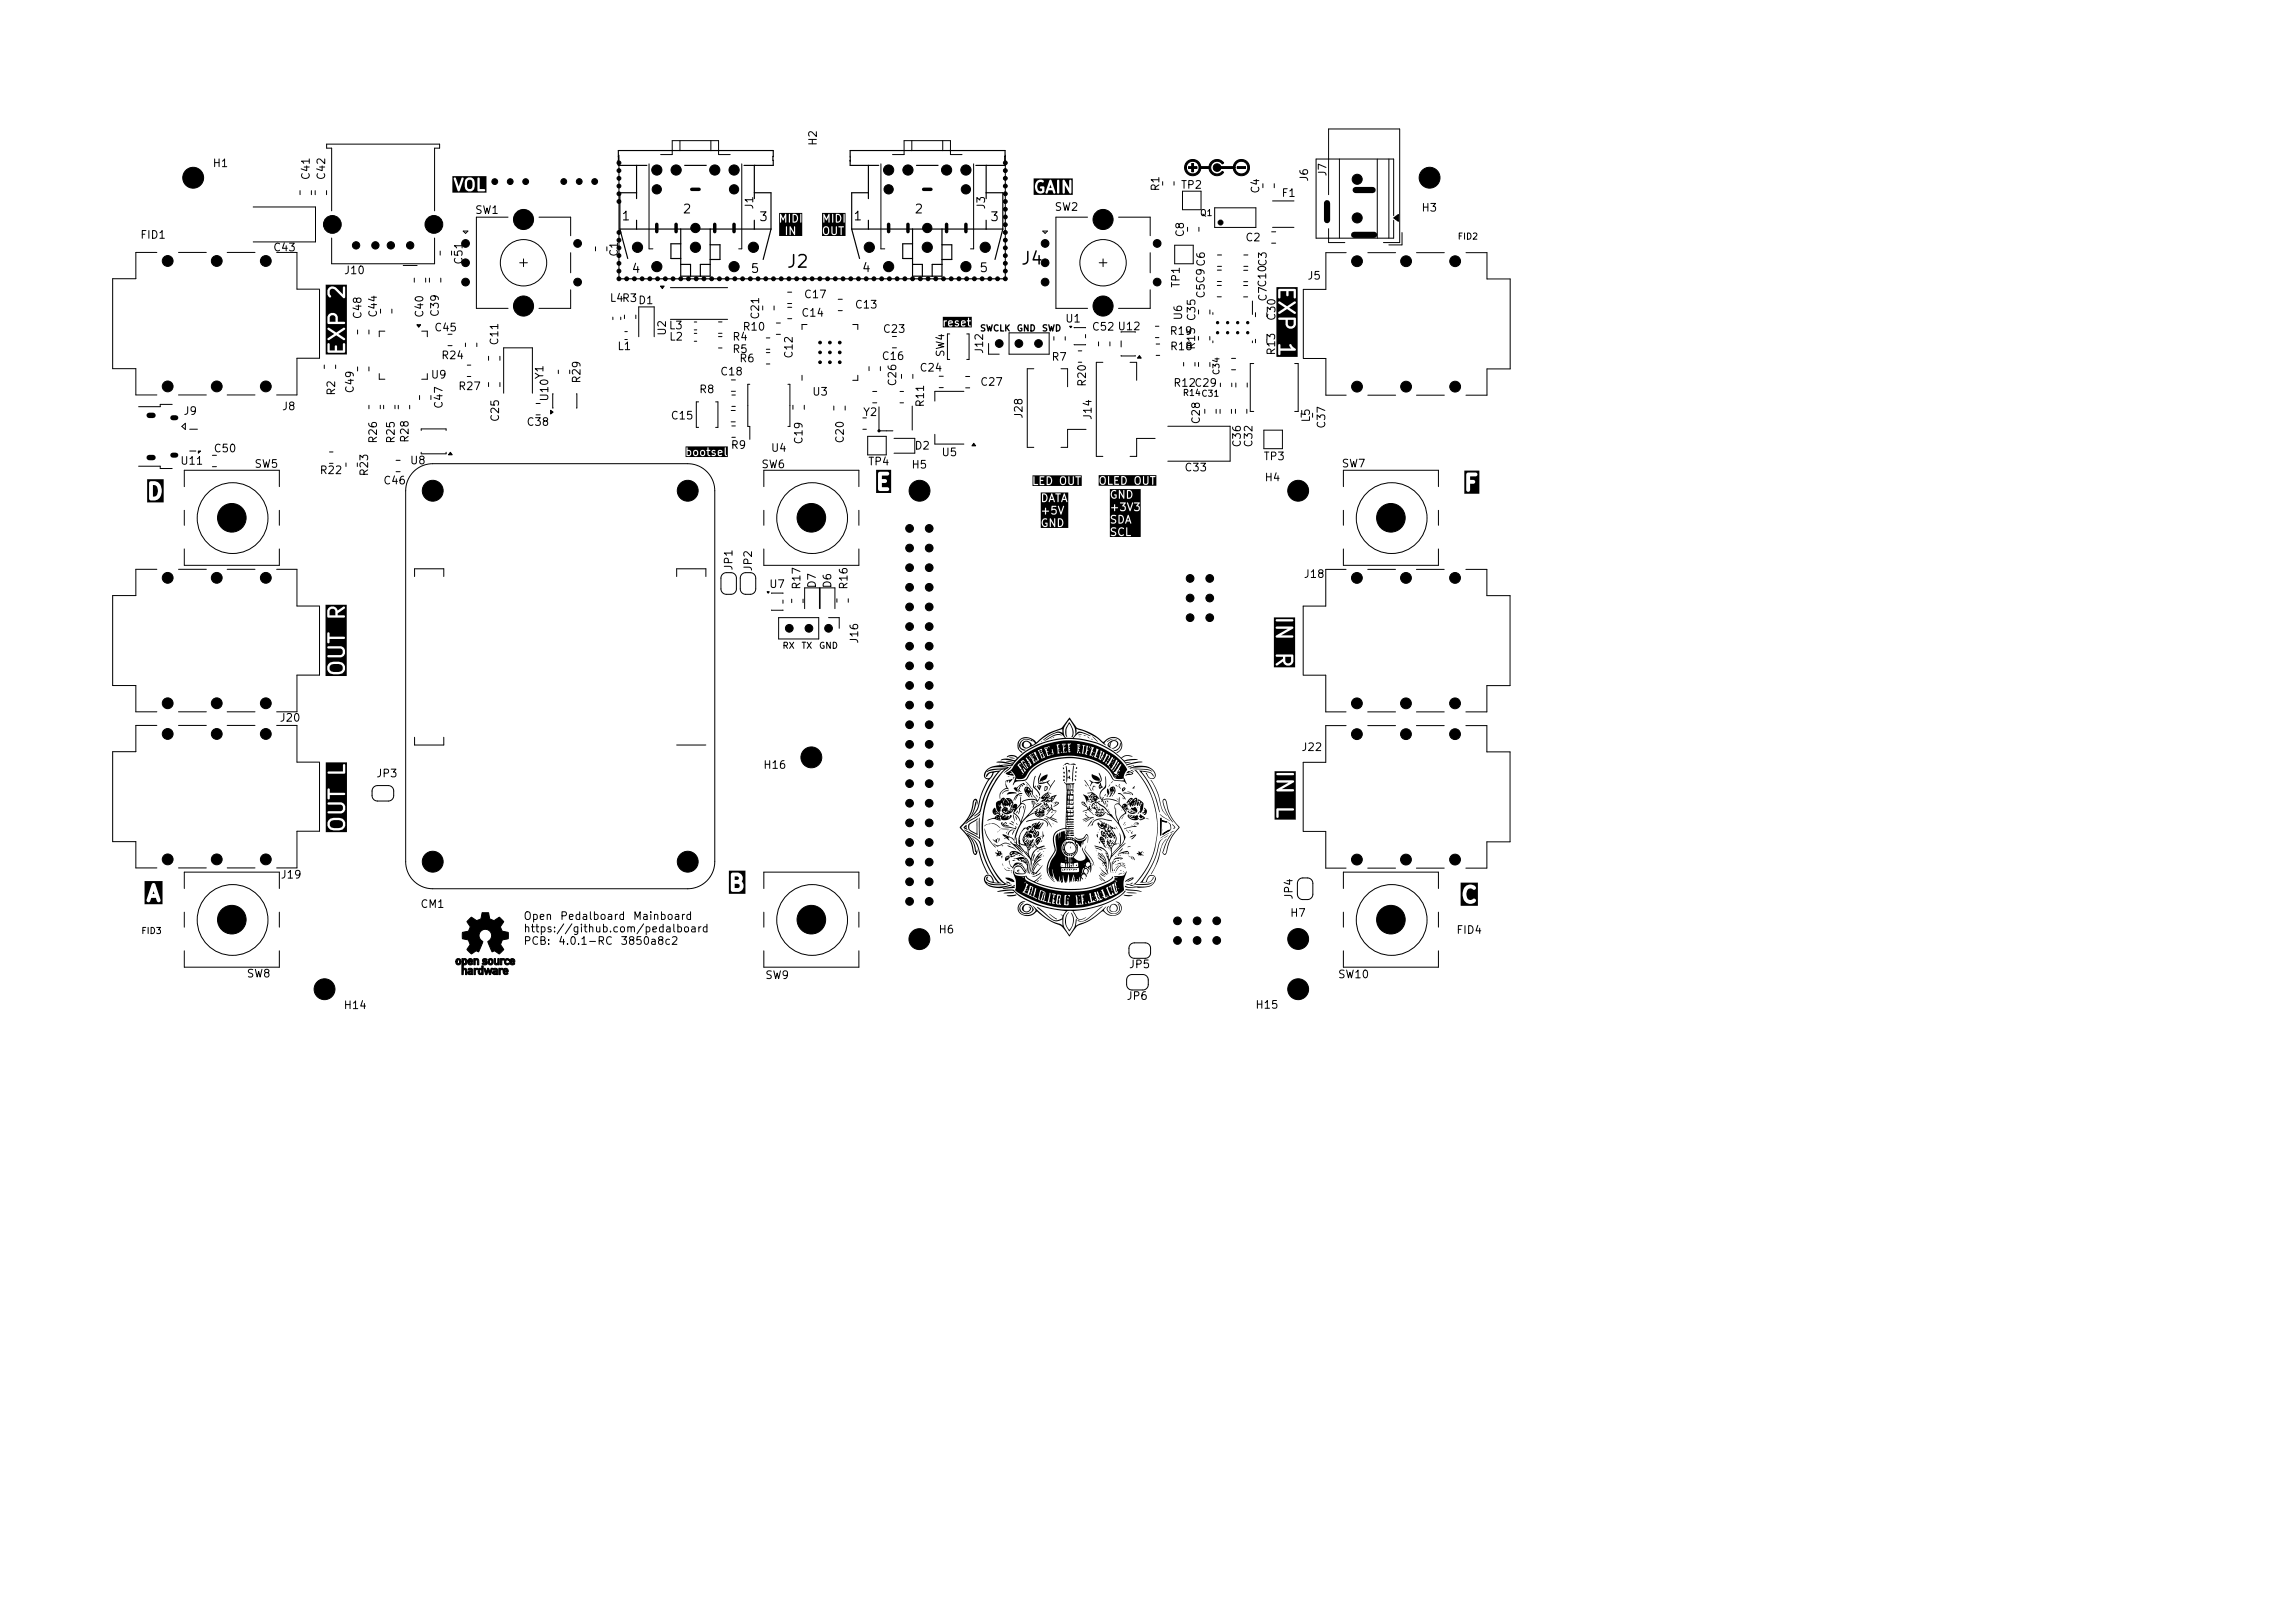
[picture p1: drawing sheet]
<svg xmlns="http://www.w3.org/2000/svg" width="297mm" height="210mm" viewBox="0 0 297 210" stroke-linecap="round" stroke-linejoin="round" font-family="sans-serif">
<defs><g id="words">
<g font-size="1.6">
<text x="101.7" y="35">J2</text>
<text x="132" y="34.6">J4</text>
</g>
<g font-size="1.1">
<text x="80.4" y="28.8">1</text>
<text x="88.3" y="27.9">2</text>
<text x="98.2" y="28.9">3</text>
<text x="110.4" y="28.8">1</text>
<text x="118.3" y="27.9">2</text>
<text x="128.1" y="28.9">3</text>
<text x="81.7" y="35.6">4</text>
<text x="97.1" y="35.6">5</text>
<text x="111.5" y="35.5">4</text>
<text x="126.7" y="35.5">5</text>
</g>
<g font-size="1">
<text x="27.4" y="21.9">H1</text>
<text x="40.3" y="23.4" transform="rotate(-90 40.3 23.4)">C41</text>
<text x="42.3" y="23.4" transform="rotate(-90 42.3 23.4)">C42</text>
<text x="105.9" y="19" transform="rotate(-90 105.9 19)">H2</text>
<text x="169.5" y="23.6" transform="rotate(-90 169.5 23.6)">J6</text>
<text x="171.9" y="22.9" transform="rotate(-90 171.9 22.9)">J7</text>
<text x="61.4" y="27.9">SW1</text>
<text x="97.7" y="27.2" transform="rotate(-90 97.7 27.2)">J1</text>
<text x="127.7" y="27.2" transform="rotate(-90 127.7 27.2)">J3</text>
<text x="136.4" y="27.5">SW2</text>
<text x="150.3" y="24.8" transform="rotate(-90 150.3 24.8)">R1</text>
<text x="152.7" y="24.7">TP2</text>
<text x="163.2" y="25.1" transform="rotate(-90 163.2 25.1)">C4</text>
<text x="165.8" y="25.7">F1</text>
<text x="183.9" y="27.6">H3</text>
<text x="18.1" y="31.1">FID1</text>
<text x="35.3" y="32.8">C43</text>
<text x="44.4" y="35.7">J10</text>
<text x="60.1" y="34.3" transform="rotate(-90 60.1 34.3)">C51</text>
<text x="80.2" y="33.3" transform="rotate(-90 80.2 33.3)">C1</text>
<text x="153.5" y="30.8" transform="rotate(-90 153.5 30.8)">C8</text>
<text x="161.1" y="31.5">C2</text>
<text x="47" y="41.4" transform="rotate(-90 47 41.4)">C48</text>
<text x="49" y="41.2" transform="rotate(-90 49 41.2)">C44</text>
<text x="55" y="41.2" transform="rotate(-90 55 41.2)">C40</text>
<text x="57" y="41.1" transform="rotate(-90 57 41.1)">C39</text>
<text x="78.8" y="39.3">L4R3</text>
<text x="82.5" y="39.6">D1</text>
<text x="98.5" y="41.4" transform="rotate(-90 98.5 41.4)">C21</text>
<text x="103.6" y="41.2">C14</text>
<text x="104" y="38.8">C17</text>
<text x="110.6" y="40.2">C13</text>
<text x="137.8" y="42">U1</text>
<text x="152.9" y="37.3" transform="rotate(-90 152.9 37.3)">TP1</text>
<text x="153.2" y="41.5" transform="rotate(-90 153.2 41.5)">U6</text>
<text x="156.2" y="38.7" transform="rotate(-90 156.2 38.7)">C5C9C6</text>
<text x="164.2" y="39.1" transform="rotate(-90 164.2 39.1)">C7C10C3</text>
<text x="165.3" y="41.6" transform="rotate(-90 165.3 41.6)">C30</text>
<text x="169.1" y="36.4">J5</text>
<text x="56.1" y="43.1">C45</text>
<text x="57" y="46.7">R24</text>
<text x="64.7" y="44.8" transform="rotate(-90 64.7 44.8)">C11</text>
<text x="79.8" y="45.5">L1</text>
<text x="86.4" y="43.5" transform="rotate(-90 86.4 43.5)">U2</text>
<text x="86.5" y="42.9">L3</text>
<text x="86.5" y="44.3">L2</text>
<text x="94.7" y="44.3">R4</text>
<text x="94.7" y="45.9">R5</text>
<text x="95.6" y="47.1">R6</text>
<text x="96" y="43">R10</text>
<text x="102.8" y="46.5" transform="rotate(-90 102.8 46.5)">C12</text>
<text x="114" y="46.8">C16</text>
<text x="114.2" y="43.3">C23</text>
<text x="122.5" y="46.3" transform="rotate(-90 122.5 46.3)">SW4</text>
<text x="127.5" y="45.9" transform="rotate(-90 127.5 45.9)">J12</text>
<text x="136" y="46.9">R7</text>
<text x="141.2" y="43">C52 U12</text>
<text x="151.3" y="43.6">R19</text>
<text x="151.3" y="45.6">R18</text>
<text x="154.9" y="45.3" transform="rotate(-90 154.9 45.3)">R15 C35</text>
<text x="165.3" y="46.1" transform="rotate(-90 165.3 46.1)">R13</text>
<text x="23.7" y="53.9">J9</text>
<text x="36.4" y="53.3">J8</text>
<text x="43.6" y="51.3" transform="rotate(-90 43.6 51.3)">R2</text>
<text x="46" y="51" transform="rotate(-90 46 51)">C49</text>
<text x="55.7" y="49.2">U9</text>
<text x="57.5" y="53" transform="rotate(-90 57.5 53)">C47</text>
<text x="59.2" y="50.7">R27</text>
<text x="70.6" y="49.1" transform="rotate(-90 70.6 49.1)">Y1</text>
<text x="71.2" y="52" transform="rotate(-90 71.2 52)">U10</text>
<text x="75.4" y="49.7" transform="rotate(-90 75.4 49.7)">R29</text>
<text x="90.4" y="51.1">R8</text>
<text x="93.1" y="48.8">C18</text>
<text x="105" y="51.4">U3</text>
<text x="116.2" y="50.1" transform="rotate(-90 116.2 50.1)">C26</text>
<text x="118.9" y="48.3">C24</text>
<text x="119.8" y="52.8" transform="rotate(-90 119.8 52.8)">R11</text>
<text x="126.8" y="50.2">C27</text>
<text x="140.8" y="50.1" transform="rotate(-90 140.8 50.1)">R20</text>
<text x="151.8" y="50.3">R12C29</text>
<text x="27.6" y="58.8">C50</text>
<text x="49" y="57.5" transform="rotate(-90 49 57.5)">R26</text>
<text x="51.3" y="57.5" transform="rotate(-90 51.3 57.5)">R25</text>
<text x="53.1" y="57.4" transform="rotate(-90 53.1 57.4)">R28</text>
<text x="64.8" y="54.7" transform="rotate(-90 64.8 54.7)">C25</text>
<text x="68.1" y="55.3">C38</text>
<text x="86.7" y="54.5">C15</text>
<text x="94.5" y="58.3">R9</text>
<text x="99.7" y="58.7">U4</text>
<text x="104.1" y="57.6" transform="rotate(-90 104.1 57.6)">C19</text>
<text x="109.4" y="57.5" transform="rotate(-90 109.4 57.5)">C20</text>
<text x="111.6" y="54.1">Y2</text>
<text x="118.3" y="58.4">D2</text>
<text x="121.8" y="59.3">U5</text>
<text x="132.6" y="54.3" transform="rotate(-90 132.6 54.3)">J28</text>
<text x="141.5" y="54.4" transform="rotate(-90 141.5 54.4)">J14</text>
<text x="155.5" y="55" transform="rotate(-90 155.5 55)">C28</text>
<text x="160.8" y="58" transform="rotate(-90 160.8 58)">C36</text>
<text x="162.3" y="58" transform="rotate(-90 162.3 58)">C32</text>
<text x="163.4" y="59.8">TP3</text>
<text x="169.8" y="54.7" transform="rotate(-90 169.8 54.7)">L5</text>
<text x="171.8" y="55.5" transform="rotate(-90 171.8 55.5)">C37</text>
<text x="23.2" y="60.4">U11</text>
<text x="32.9" y="60.8">SW5</text>
<text x="41.3" y="61.6">R22</text>
<text x="47.9" y="61.7" transform="rotate(-90 47.9 61.7)">R23</text>
<text x="49.5" y="62.9">C46</text>
<text x="53" y="60.3">U8</text>
<text x="98.5" y="60.8">SW6</text>
<text x="112.3" y="60.5">TP4</text>
<text x="117.9" y="60.9">H5</text>
<text x="153.2" y="61.2">C33</text>
<text x="163.6" y="62.5">H4</text>
<text x="173.6" y="60.7">SW7</text>
<text x="95" y="73.9" transform="rotate(-90 95 73.9)">JP1</text>
<text x="97.6" y="74" transform="rotate(-90 97.6 74)">JP2</text>
<text x="99.5" y="76.3">U7</text>
<text x="103.8" y="76.4" transform="rotate(-90 103.8 76.4)">R17</text>
<text x="105.8" y="76.2" transform="rotate(-90 105.8 76.2)">D7</text>
<text x="107.8" y="76.2" transform="rotate(-90 107.8 76.2)">D6</text>
<text x="109.9" y="76.4" transform="rotate(-90 109.9 76.4)">R16</text>
<text x="168.6" y="75">J18</text>
<text x="111.3" y="83.4" transform="rotate(-90 111.3 83.4)">J16</text>
<text x="36.1" y="93.6">J20</text>
<text x="48.6" y="100.8">JP3</text>
<text x="98.7" y="99.7">H16</text>
<text x="168.3" y="97.4">J22</text>
<text x="36.2" y="113.9">J19</text>
<text x="54.3" y="117.7">CM1</text>
<text x="67.7" y="119.3">Open</text>
<text x="72.4" y="119.3">Pedalboard</text>
<text x="81.8" y="119.3">Mainboard</text>
<text x="166.9" y="118.9">H7</text>
<text x="167.5" y="116.5" transform="rotate(-90 167.5 116.5)">JP4</text>
<text x="67.7" y="120.9">https://github.com/pedalboard</text>
<text x="67.7" y="122.5">PCB:</text>
<text x="72.2" y="122.5">4.0.1-RC</text>
<text x="80.2" y="122.5">3850a8c2</text>
<text x="121.4" y="121">H6</text>
<text x="146" y="125.5">JP5</text>
<text x="188.4" y="121.1">FID4</text>
<text x="31.9" y="126.7">SW8</text>
<text x="44.4" y="130.8">H14</text>
<text x="99" y="126.9">SW9</text>
<text x="145.7" y="129.6">JP6</text>
<text x="162.4" y="130.8">H15</text>
<text x="173.1" y="126.8">SW10</text>
</g>
<g font-size=".8">
<text x="155.2" y="28.1">Q1</text>
<text x="188.6" y="31.2">FID2</text>
<text x="126.8" y="43.1">SWCLK</text>
<text x="131.5" y="43.1">GND</text>
<text x="134.8" y="43.1">SWD</text>
<text x="153" y="51.4">R14C31</text>
<text x="158" y="48.6" transform="rotate(-90 158 48.6)">C34</text>
<text x="101.2" y="84.1">RX</text>
<text x="103.7" y="84.1">TX</text>
<text x="105.9" y="84.1">GND</text>
<text x="18.2" y="121">FID3</text>
</g>
</g></defs>
<g fill="#000" stroke="#000" stroke-width=".13">
<path d="M85.5 37h.5l-.3 .3zM153.6 20.9l.3-.2 .5-.1 .4 .1 .3 .2 .2 .4 .1 .4-.1 .4-.2 .3-.3 .3h-.4h-.5l-.3-.3-.2-.3-.1-.4h.2l.1 .3 .3 .3 .5 .2 .5-.2 .3-.6-.3-.6-.5-.2-.6 .2-.2 .2-.1 .4h-.2l.1-.4zM154.2 21.2h.3v1h-.3zM153.8 21.6h1.1v.2h-1.1zM155.3 21.6h1.2v.2h-1.2zM156.8 20.9l.3-.2 .4-.1 .4 .1 .4 .3 .1 .1-.2 .1-.5-.3h-.5l-.4 .3-.1 .4 .1 .5 .3 .3 .6 .1 .5-.3 .2 .1-.2 .1-.3 .2-.4 .1h-.4l-.3-.3-.3-.3v-.4v-.4zM157.8 21.6h1.8v.2h-1.8zM159.9 20.9l.3-.2 .5-.1 .4 .1 .3 .2 .2 .4 .1 .4-.1 .4-.2 .3-.3 .3h-.4h-.5l-.3-.3-.2-.3-.1-.4h.2l.1 .3 .3 .3 .5 .2 .5-.2 .3-.6-.3-.6-.5-.2-.6 .2-.2 .2-.1 .4h-.2l.1-.4zM160.1 21.6h1.1v.2h-1.1zM180.4 28.2l.6-.4v.8zM25.7 58.4h.2l-.2 .2zM54 42h.4l-.2 .3z"/>
<path d="M58.3 58.5l.2 .4h-.5zM71.3 53.1l.3 .2-.3 .3zM126 57.4l.3 .3h-.5zM138.4 42.2h.3l-.1 .2zM147.5 46l.2 .3h-.5zM99.3 76.6h.3l-.2 .2zM60.8 118.9l.1-.1a.18 .18 0 0 1 .1-.1 .18 .18 0 0 1 .2 .1l.5 .3 .5-.2 .2-.8h.8l.2 .8 .5 .2 .5-.3a.17 .17 0 0 1 .2-.1 .17 .17 0 0 1 .2 .1l.2 .2a.26 .26 0 0 1 .2 .3 .26 .26 0 0 1-.2 .2v.1a.6 .6 0 0 0 .1 .9l.4 .1a.26 .26 0 0 1 .3 .1 .26 .26 0 0 1 0 .3v.2a.23 .23 0 0 1 0 .3 .23 .23 0 0 1-.3 0 .58 .58 0 0 0-.7 .7l.3 .4a.25 .25 0 0 1 .1 .3 .25 .25 0 0 1-.2 .2l-.2 .2a.2 .2 0 0 1-.2 .1 .2 .2 0 0 1-.2-.1l-.1-.1a.46 .46 0 0 0-.6 0l-.5-1a.21 .21 0 0 1-.1-.2 .21 .21 0 0 1 .1-.2 .82 .82 0 0 0 .2-1.3 .82 .82 0 0 0-1.3 .1 .82 .82 0 0 0 .4 1.2l-.6 1.4a.52 .52 0 0 0-.7 .1 .24 .24 0 0 1-.3 .1 .24 .24 0 0 1-.1-.2h-.1a.29 .29 0 0 1-.2-.4l.1-.1a.68 .68 0 0 0 .1-.9 .68 .68 0 0 0-.8-.3 .21 .21 0 0 1-.1-.4v-.2a.26 .26 0 0 1 .1-.3 .26 .26 0 0 1 .3 0 .6 .6 0 0 0 .6-.7l-.3-.5a.17 .17 0 0 1-.1-.2 .17 .17 0 0 1 .2-.1zM150.2 105.9v2.2zM150.4 106.2l.6 .2-.4-.1zM150.5 107.9l.9-.5zM59.1 124.1a.38 .38 0 0 1 .5 .1 .38 .38 0 0 1-.1 .5 .38 .38 0 0 1-.5-.1v-.2h.2a.19 .19 0 0 0 .2 .3 .19 .19 0 0 0 .1-.3 .15 .15 0 0 0-.2-.2 .15 .15 0 0 0-.1 .1v.1h-.2zM59.8 124l.2 .1a.33 .33 0 0 1 .4 .1 .33 .33 0 0 1 0 .3 .27 .27 0 0 1-.1 .3 .27 .27 0 0 1-.3 0v.5h.2l.2 .2v.6h-.2v-.6a.18 .18 0 0 0-.2 0 .18 .18 0 0 0 0 .3v.3h-.2v-1.6h.2a.17 .17 0 0 0 .2 .1 .17 .17 0 0 0 0-.2v-.1a.13 .13 0 0 0-.1-.1 .13 .13 0 0 0-.1 .1v.2h-.2z"/>
<path d="M60.6 125.4a.37 .37 0 0 1 .5-.1 .37 .37 0 0 1 .1 .5v.3h-.3a.28 .28 0 0 1-.4-.3l.2 .1a.16 .16 0 0 0 .2 0 .16 .16 0 0 0 .1-.1h-.3h-.2a.34 .34 0 0 1 .5-.2 .2 .2 0 0 0-.1-.1 .2 .2 0 0 0-.2 0zM60.6 124.1a.36 .36 0 0 1 .5 0 .36 .36 0 0 1 .1 .4h-.5a.21 .21 0 0 0 .1 .2 .21 .21 0 0 0 .3-.1l.1 .1a.36 .36 0 0 1-.5 .1 .36 .36 0 0 1-.2-.5h.5a.16 .16 0 0 0-.2-.1 .16 .16 0 0 0-.1 .1h-.2zM61.3 125.3l.6 .1-.4 .1v.6h-.2zM61.3 124h.1a.48 .48 0 0 1 .6 .3v.5h-.2v-.3a.18 .18 0 0 0-.2-.3 .17 .17 0 0 0-.1 .3v.3h-.2zM62 125.3l.3 .1v-.4h.2v1.1h-.2a.3 .3 0 0 1-.3-.1 .3 .3 0 0 1-.1-.3h.2a.17 .17 0 0 0 .2 .2 .17 .17 0 0 0 0-.3 .16 .16 0 0 0-.1-.1 .16 .16 0 0 0-.1 .2h-.2zM62.5 124.1l.3-.1 .2 .1a.15 .15 0 0 1-.1 .2 .15 .15 0 0 1-.1-.1h-.2v.1a.32 .32 0 0 1 .5 .4 .31 .31 0 0 1-.5 .1l-.2-.1 .1-.1a.19 .19 0 0 0 .2 .1 .19 .19 0 0 0 .2-.2 .3 .3 0 0 1-.4 0 .3 .3 0 0 1 0-.4zM62.6 125.3h.2l.1 .5 .2-.5h.1l.2 .5 .2-.5h.1l-.2 .8h-.2l-.1-.5-.2 .5h-.1zM63.2 124.1a.4 .4 0 0 1 .6 .2 .4 .4 0 0 1-.2 .5 .35 .35 0 0 1-.4-.4h.1v.1a.16 .16 0 0 0 .2 .2 .16 .16 0 0 0 .2-.2 .18 .18 0 0 0-.2-.3 .17 .17 0 0 0-.2 .2h-.1zM64 124h.1v.3a.22 .22 0 0 0 0 .3 .22 .22 0 0 0 .3 .1v-.7h.2v.8h-.2a.33 .33 0 0 1-.4 0 .33 .33 0 0 1 0-.4zM63.8 125.4a.37 .37 0 0 1 .5-.1 .37 .37 0 0 1 .1 .5v.3h-.2a.29 .29 0 0 1-.5-.2h.2a.17 .17 0 0 0 .2 0 .17 .17 0 0 0 .1-.1l-.5 .1 .2-.3h.3a.25 .25 0 0 0-.3-.1zM64.6 125.3l.5 .1-.2 .1a.22 .22 0 0 0-.2 .1 .22 .22 0 0 0 0 .2v.3h-.1zM64.8 124l.5 .1-.1 .1-.3 .1v.5h-.1z"/>
<path d="M65.2 125.4a.36 .36 0 0 1 .4-.1 .36 .36 0 0 1 .2 .5h-.5l.1 .1h.2l.1 .1a.36 .36 0 0 1-.4 .1 .36 .36 0 0 1-.2-.5h.5a.15 .15 0 0 0-.2-.1 .15 .15 0 0 0-.1 .1h-.2zM65.4 124.1a.28 .28 0 0 1 .3-.1 .28 .28 0 0 1 .2 .2l-.1 .1a.23 .23 0 0 0-.3 0 .23 .23 0 0 0 0 .4 .23 .23 0 0 0 .4-.1v.1a.41 .41 0 0 1-.5 0 .41 .41 0 0 1 0-.6zM66.1 124.1a.35 .35 0 0 1 .4 0 .35 .35 0 0 1 .1 .4h-.5a.2 .2 0 0 0 .2 .2 .2 .2 0 0 0 .2-.1l.1 .1a.38 .38 0 0 1-.5 .1 .38 .38 0 0 1-.1-.5h.5a.16 .16 0 0 0-.2-.1 .16 .16 0 0 0-.2 .1h-.1z"/>
<circle cx="21.7" cy="33.8" r=".7"/>
<circle cx="25" cy="23" r="1.35"/>
<circle cx="28" cy="33.8" r=".7"/>
<circle cx="34.4" cy="33.8" r=".7"/>
<circle cx="43" cy="29" r="1.15"/>
<circle cx="46.1" cy="31.8" r=".47"/>
<circle cx="48.6" cy="31.8" r=".47"/>
<circle cx="50.6" cy="31.8" r=".47"/>
<circle cx="53.1" cy="31.8" r=".47"/>
<circle cx="56.1" cy="29" r="1.15"/>
<circle cx="60.2" cy="36.5" r=".5"/>
<circle cx="60.2" cy="31.5" r=".5"/>
<circle cx="60.2" cy="34" r=".5"/>
<circle cx="64" cy="23.5" r=".38"/>
<circle cx="66" cy="23.5" r=".38"/>
<circle cx="67.7" cy="28.4" r="1.3"/>
<circle cx="67.7" cy="39.6" r="1.3"/>
<circle cx="68" cy="23.5" r=".38"/>
<circle cx="73" cy="23.5" r=".37"/>
<circle cx="74.8" cy="36.5" r=".5"/>
<circle cx="74.8" cy="31.5" r=".5"/>
<circle cx="75" cy="23.5" r=".37"/>
<circle cx="77" cy="23.5" r=".37"/>
<circle cx="80.1" cy="22.1" r=".25"/>
<circle cx="80.1" cy="25.1" r=".25"/>
<circle cx="80.1" cy="23.1" r=".25"/>
<circle cx="80.1" cy="24.1" r=".25"/>
<circle cx="80.1" cy="21.1" r=".25"/>
<circle cx="80.1" cy="26.1" r=".25"/>
<circle cx="80.1" cy="32.1" r=".25"/>
<circle cx="80.1" cy="33.1" r=".25"/>
<circle cx="80.1" cy="35.1" r=".25"/>
<circle cx="80.1" cy="30.1" r=".25"/>
<circle cx="80.1" cy="34.1" r=".25"/>
<circle cx="80.1" cy="31.1" r=".25"/>
<circle cx="80.1" cy="36.1" r=".25"/>
<circle cx="81.1" cy="36.1" r=".25"/>
<circle cx="82.1" cy="36.1" r=".25"/>
<circle cx="82.5" cy="32" r=".66"/>
<circle cx="83.1" cy="36.1" r=".25"/>
<circle cx="84.1" cy="36.1" r=".25"/>
<circle cx="85" cy="24.5" r=".6"/>
<circle cx="85" cy="34.5" r=".66"/>
<circle cx="85" cy="22" r=".66"/>
<circle cx="85.1" cy="36.1" r=".25"/>
<circle cx="86.1" cy="36.1" r=".25"/>
<circle cx="87.1" cy="36.1" r=".25"/>
<circle cx="87.5" cy="22" r=".66"/>
<circle cx="88.1" cy="36.1" r=".25"/>
<circle cx="89.1" cy="36.1" r=".25"/>
<circle cx="90" cy="29.5" r=".6"/>
<circle cx="90" cy="32" r=".66"/>
<circle cx="90.1" cy="36.1" r=".25"/>
<circle cx="91.1" cy="36.1" r=".25"/>
<circle cx="92.1" cy="36.1" r=".25"/>
<circle cx="92.5" cy="22" r=".66"/>
<circle cx="93.1" cy="36.1" r=".25"/>
<circle cx="94.1" cy="36.1" r=".25"/>
<circle cx="95" cy="24.5" r=".6"/>
<circle cx="95" cy="34.5" r=".66"/>
<circle cx="95" cy="22" r=".66"/>
<circle cx="95.1" cy="36.1" r=".25"/>
<circle cx="96.1" cy="36.1" r=".25"/>
<circle cx="97.1" cy="36.1" r=".25"/>
<circle cx="97.5" cy="32" r=".66"/>
<circle cx="98.1" cy="36.1" r=".25"/>
<circle cx="99.1" cy="36.1" r=".25"/>
<circle cx="100.1" cy="36.1" r=".25"/>
<circle cx="101.1" cy="36.1" r=".25"/>
<circle cx="102.1" cy="36.1" r=".25"/>
<circle cx="103.1" cy="36.1" r=".25"/>
<circle cx="104.1" cy="36.1" r=".25"/>
<circle cx="105.1" cy="36.1" r=".25"/>
<circle cx="106.1" cy="36.1" r=".25"/>
<circle cx="107.1" cy="36.1" r=".25"/>
<circle cx="108.1" cy="36.1" r=".25"/>
<circle cx="109.1" cy="36.1" r=".25"/>
<circle cx="110.1" cy="36.1" r=".25"/>
<circle cx="111.1" cy="36.1" r=".25"/>
<circle cx="112.1" cy="36.1" r=".25"/>
<circle cx="112.5" cy="32" r=".66"/>
<circle cx="113.1" cy="36.1" r=".25"/>
<circle cx="114.1" cy="36.1" r=".25"/>
<circle cx="115" cy="34.5" r=".66"/>
<circle cx="115" cy="22" r=".66"/>
<circle cx="115" cy="24.5" r=".6"/>
<circle cx="115.1" cy="36.1" r=".25"/>
<circle cx="116.1" cy="36.1" r=".25"/>
<circle cx="117.1" cy="36.1" r=".25"/>
<circle cx="117.5" cy="22" r=".66"/>
<circle cx="118.1" cy="36.1" r=".25"/>
<circle cx="119.1" cy="36.1" r=".25"/>
<circle cx="120" cy="29.5" r=".6"/>
<circle cx="120" cy="32" r=".66"/>
<circle cx="120.1" cy="36.1" r=".25"/>
<circle cx="121.1" cy="36.1" r=".25"/>
<circle cx="122.1" cy="36.1" r=".25"/>
<circle cx="122.5" cy="22" r=".66"/>
<circle cx="123.1" cy="36.1" r=".25"/>
<circle cx="124.1" cy="36.1" r=".25"/>
<circle cx="125" cy="34.5" r=".66"/>
<circle cx="125" cy="22" r=".66"/>
<circle cx="125" cy="24.5" r=".6"/>
<circle cx="125.1" cy="36.1" r=".25"/>
<circle cx="126.1" cy="36.1" r=".25"/>
<circle cx="127.1" cy="36.1" r=".25"/>
<circle cx="127.5" cy="32" r=".66"/>
<circle cx="128.1" cy="36.1" r=".25"/>
<circle cx="129.1" cy="36.1" r=".25"/>
<circle cx="130.1" cy="28.1" r=".25"/>
<circle cx="130.1" cy="27.1" r=".25"/>
<circle cx="130.1" cy="22.1" r=".25"/>
<circle cx="130.1" cy="25.1" r=".25"/>
<circle cx="130.1" cy="23.1" r=".25"/>
<circle cx="130.1" cy="24.1" r=".25"/>
<circle cx="130.1" cy="26.1" r=".25"/>
<circle cx="130.1" cy="21.1" r=".25"/>
<circle cx="130.1" cy="32.1" r=".25"/>
<circle cx="130.1" cy="35.1" r=".25"/>
<circle cx="130.1" cy="33.1" r=".25"/>
<circle cx="130.1" cy="30.1" r=".25"/>
<circle cx="130.1" cy="34.1" r=".25"/>
<circle cx="130.1" cy="29.1" r=".25"/>
<circle cx="130.1" cy="36.1" r=".25"/>
<circle cx="130.1" cy="31.1" r=".25"/>
<circle cx="135.3" cy="36.5" r=".5"/>
<circle cx="135.3" cy="31.5" r=".5"/>
<circle cx="135.3" cy="34" r=".5"/>
<circle cx="142.8" cy="28.4" r="1.3"/>
<circle cx="142.8" cy="39.6" r="1.3"/>
<circle cx="149.7" cy="31.5" r=".5"/>
<circle cx="149.7" cy="36.5" r=".5"/>
<circle cx="157.5" cy="21.7" r=".49"/>
<circle cx="158" cy="28.8" r=".32"/>
<circle cx="175.6" cy="33.8" r=".7"/>
<circle cx="175.6" cy="23.2" r=".65"/>
<circle cx="175.6" cy="28.2" r=".65"/>
<circle cx="182" cy="33.8" r=".7"/>
<circle cx="185" cy="23" r="1.35"/>
<circle cx="188.3" cy="33.8" r=".7"/>
<circle cx="21.7" cy="50" r=".7"/>
<circle cx="28" cy="50" r=".7"/>
<circle cx="34.4" cy="50" r=".7"/>
<circle cx="106.1" cy="46.9" r=".17"/>
<circle cx="106.1" cy="44.3" r=".17"/>
<circle cx="106.1" cy="45.6" r=".17"/>
<circle cx="107.4" cy="46.9" r=".17"/>
<circle cx="107.4" cy="45.6" r=".17"/>
<circle cx="107.4" cy="44.3" r=".17"/>
<circle cx="108.7" cy="46.9" r=".17"/>
<circle cx="108.7" cy="44.3" r=".17"/>
<circle cx="108.7" cy="45.6" r=".17"/>
<circle cx="129.3" cy="44.5" r=".5"/>
<circle cx="131.9" cy="44.5" r=".5"/>
<circle cx="134.4" cy="44.5" r=".5"/>
<circle cx="157.6" cy="41.8" r=".15"/>
<circle cx="157.6" cy="43.1" r=".15"/>
<circle cx="158.9" cy="43.1" r=".15"/>
<circle cx="158.9" cy="41.8" r=".15"/>
<circle cx="160.2" cy="43.1" r=".15"/>
<circle cx="160.2" cy="41.8" r=".15"/>
<circle cx="161.5" cy="43.1" r=".15"/>
<circle cx="161.5" cy="41.8" r=".15"/>
<circle cx="175.6" cy="50" r=".7"/>
<circle cx="182" cy="50" r=".7"/>
<circle cx="188.3" cy="50" r=".7"/>
<circle cx="21.7" cy="74.8" r=".7"/>
<circle cx="28" cy="74.8" r=".7"/>
<circle cx="30" cy="67" r="1.85"/>
<circle cx="34.4" cy="74.8" r=".7"/>
<circle cx="56" cy="63.5" r="1.35"/>
<circle cx="89" cy="63.5" r="1.35"/>
<circle cx="105" cy="67" r="1.85"/>
<circle cx="117.7" cy="70.9" r=".5"/>
<circle cx="117.7" cy="78.5" r=".5"/>
<circle cx="117.7" cy="76" r=".5"/>
<circle cx="117.7" cy="68.4" r=".5"/>
<circle cx="117.7" cy="73.5" r=".5"/>
<circle cx="119" cy="63.5" r="1.35"/>
<circle cx="120.3" cy="68.4" r=".5"/>
<circle cx="120.3" cy="78.5" r=".5"/>
<circle cx="120.3" cy="70.9" r=".5"/>
<circle cx="120.3" cy="73.5" r=".5"/>
<circle cx="120.3" cy="76" r=".5"/>
<circle cx="154" cy="74.8" r=".5"/>
<circle cx="154" cy="77.4" r=".5"/>
<circle cx="154" cy="79.9" r=".5"/>
<circle cx="156.6" cy="74.8" r=".5"/>
<circle cx="156.6" cy="77.4" r=".5"/>
<circle cx="156.6" cy="79.9" r=".5"/>
<circle cx="168" cy="63.5" r="1.35"/>
<circle cx="175.6" cy="74.8" r=".7"/>
<circle cx="180" cy="67" r="1.85"/>
<circle cx="181.9" cy="74.8" r=".7"/>
<circle cx="188.3" cy="74.8" r=".7"/>
<circle cx="21.7" cy="95" r=".7"/>
<circle cx="21.7" cy="91" r=".7"/>
<circle cx="28" cy="95" r=".7"/>
<circle cx="28" cy="91" r=".7"/>
<circle cx="34.4" cy="95" r=".7"/>
<circle cx="34.4" cy="91" r=".7"/>
<circle cx="102.1" cy="81.3" r=".5"/>
<circle cx="104.7" cy="81.3" r=".5"/>
<circle cx="105" cy="98" r="1.35"/>
<circle cx="107.2" cy="81.3" r=".5"/>
<circle cx="117.7" cy="83.6" r=".5"/>
<circle cx="117.7" cy="93.8" r=".5"/>
<circle cx="117.7" cy="86.2" r=".5"/>
<circle cx="117.7" cy="91.2" r=".5"/>
<circle cx="117.7" cy="98.9" r=".5"/>
<circle cx="117.7" cy="81.1" r=".5"/>
<circle cx="117.7" cy="96.3" r=".5"/>
<circle cx="117.7" cy="88.7" r=".5"/>
<circle cx="120.2" cy="93.8" r=".05"/>
<circle cx="120.3" cy="96.3" r=".5"/>
<circle cx="120.3" cy="93.8" r=".5"/>
<circle cx="120.3" cy="81.1" r=".5"/>
<circle cx="120.3" cy="83.6" r=".5"/>
<circle cx="120.3" cy="86.2" r=".5"/>
<circle cx="120.3" cy="88.7" r=".5"/>
<circle cx="120.3" cy="98.9" r=".5"/>
<circle cx="120.3" cy="91.2" r=".5"/>
<circle cx="175.6" cy="91" r=".7"/>
<circle cx="175.6" cy="95" r=".7"/>
<circle cx="181.9" cy="91" r=".7"/>
<circle cx="181.9" cy="95" r=".7"/>
<circle cx="188.3" cy="91" r=".7"/>
<circle cx="188.3" cy="95" r=".7"/>
<circle cx="21.7" cy="111.2" r=".7"/>
<circle cx="28" cy="111.2" r=".7"/>
<circle cx="30" cy="119" r="1.85"/>
<circle cx="34.4" cy="111.2" r=".7"/>
<circle cx="56" cy="111.5" r="1.35"/>
<circle cx="89" cy="111.5" r="1.35"/>
<circle cx="105" cy="119" r="1.85"/>
<circle cx="117.7" cy="114.1" r=".5"/>
<circle cx="117.7" cy="103.9" r=".5"/>
<circle cx="117.7" cy="101.4" r=".5"/>
<circle cx="117.7" cy="116.6" r=".5"/>
<circle cx="117.7" cy="106.5" r=".5"/>
<circle cx="117.7" cy="109" r=".5"/>
<circle cx="117.7" cy="111.6" r=".5"/>
<circle cx="120.3" cy="103.9" r=".5"/>
<circle cx="120.3" cy="111.6" r=".5"/>
<circle cx="120.3" cy="101.4" r=".5"/>
<circle cx="120.3" cy="109" r=".5"/>
<circle cx="120.3" cy="116.6" r=".5"/>
<circle cx="120.3" cy="106.5" r=".5"/>
<circle cx="120.3" cy="114.1" r=".5"/>
<circle cx="152.4" cy="119.2" r=".5"/>
<circle cx="154.9" cy="119.2" r=".5"/>
<circle cx="157.5" cy="119.2" r=".5"/>
<circle cx="175.6" cy="111.2" r=".7"/>
<circle cx="180" cy="119" r="1.85"/>
<circle cx="181.9" cy="111.2" r=".7"/>
<circle cx="188.3" cy="111.2" r=".7"/>
<circle cx="42" cy="128" r="1.35"/>
<circle cx="119" cy="121.5" r="1.35"/>
<circle cx="152.4" cy="121.7" r=".5"/>
<circle cx="154.9" cy="121.7" r=".5"/>
<circle cx="157.5" cy="121.7" r=".5"/>
<circle cx="168" cy="121.5" r="1.35"/>
<circle cx="168" cy="128" r="1.35"/>
</g>
<g fill="#000">
<path d="M60.5 23.4l.2-.1h.3a.83 .83 0 0 1-.1 1.2l-.3-.1a1.02 1.02 0 0 1-.1-1zM58.5 22.8h4.5v2.1h-4.5v-1.8h.2l.6 1.7 .2-.1 .4-1.1h.2l.1 .8 .2 .3 .2 .1 .6-.1 .2-.2v-.4v-.5l-.2-.5h.6v1.6l.8 .1a.15 .15 0 0 0 .2-.2 .15 .15 0 0 0-.2-.1h-.5v-1.4a.15 .15 0 0 0-.2-.1 .15 .15 0 0 0-.1 .1h-.6l-.2-.1h-.4l-.4 .2-.1 .4h-.2l.1-.4a.15 .15 0 0 0-.1-.2 .15 .15 0 0 0-.2 .1l-.3 1-.4-1a.15 .15 0 0 0-.2-.1 .15 .15 0 0 0-.1 .1h-.2zM102.7 27.8a.43 .43 0 0 1 .4 .4 .43 .43 0 0 1-.4 .5zM100.8 27.6h3v2.9h-3v-1.2h.9l.1 1.1 .1-.1v-1h.3v1.1h.1v-.8l.5 .8h.1v-1.1h-.1v.8l-.5-.8h-1.5v-1.6h.1l.1 1.1h.1v-.7l.2 .4 .3-.4v.7h.1l.1-1.1h.3v1.1l.1-.1v-1h.4v1v.1h.5l.1-.3 .1-.3-.2-.5h.5v1.1h.1v-.1v-1h-.1h-.7h-1.1h-.1l-.3 .6-.3-.6h-.3zM106.7 29.5l.1-.1 .2 .1a.57 .57 0 0 1 0 .8l-.2-.1a.7 .7 0 0 1-.1-.7zM108.3 27.8a.43 .43 0 0 1 .4 .4 .43 .43 0 0 1-.4 .5zM106.4 27.6h3v2.9h-3v-.8h.1v.5l.2 .2h.3l.3-.2v-.5l-.1-.4h.4v.9l.3 .2h.3l.1-.2v-.9l.5 .1v1h.1v-1h.3l-.1-.1h-.9v.8l-.2 .2h-.1l-.2-.2v-.8h-.1h-.8l-.2 .2-.1 .2h-.1v-2h.1l.1 1.1h.1v-.7l.2 .4 .3-.4v.7h.1l.1-1.1h.3v1.1l.1-.1v-1h.4v1v.1h.5l.1-.3 .1-.3-.2-.5h.5v1.1h.1v-.1v-1h-.1h-.7h-1.1h-.1l-.3 .6-.3-.6h-.3zM135.9 23.9l.2 .4h-.3zM133.8 23.1h5v2.1h-5v-1.2h.1l.1 .6 .3 .4h.4l.6-.1a.15 .15 0 0 0 .1 .1 .15 .15 0 0 0 .2-.1l.1-.3h.5l.1 .3a.15 .15 0 0 0 .2 .1 .15 .15 0 0 0 .1-.1l-.5-1.5h.7v1.5a.15 .15 0 0 0 .1 .2 .15 .15 0 0 0 .2-.2v-1.5h.4v1.5a.15 .15 0 0 0 .2 .2 .15 .15 0 0 0 .1-.2v-.9l.6 1h.1h.1l.1-1.6a.15 .15 0 0 0-.2-.1 .15 .15 0 0 0-.1 .1v.9l-.7-1h-.1l-.1 .1h-.4a.15 .15 0 0 0-.2-.1 .15 .15 0 0 0-.1 .1h-.7l-.1-.1h-.2l-.5 1.6h-.2v-.7l-.4-.1a.15 .15 0 0 0-.1 .2 .15 .15 0 0 0 .1 .1h.2v.3a.38 .38 0 0 1-.6-.2l-.1-.4a.47 .47 0 0 1 .6-.5h.1a.15 .15 0 0 0 .2-.1 .15 .15 0 0 0-.1-.2h-.4h-.3l-.2 .2-.2 .5h-.1zM42.7 40.9a.39 .39 0 0 1 .7 .2v.5h-.7zM42.1 36.8h2.8v9.1h-2.8v-1.4h.3v1l.1 .1h2.1l.1-1.1a.15 .15 0 0 0-.2-.1 .15 .15 0 0 0-.1 .1v.8h-.8v-.5a.15 .15 0 0 0-.1-.1 .15 .15 0 0 0-.2 .1v.5h-.6v-.8a.15 .15 0 0 0-.2-.1 .15 .15 0 0 0-.1 .1h-.3v-2h.3l.8 .7-.8 .6a.15 .15 0 0 0 0 .2 .15 .15 0 0 0 .2 0l.9-.6 .9 .6a.15 .15 0 0 0 .2 0 .15 .15 0 0 0 0-.2l-.8-.6 .8-.5a.15 .15 0 0 0 0-.2 .15 .15 0 0 0-.2-.1l-.9 .6-.9-.6-.2 .1h-.3v-1.5h.3v.8l.1 .1h2a.15 .15 0 0 0 .2-.1 .15 .15 0 0 0-.2-.2h-.8v-.6l-.2-.4-.3-.1h-.4l-.3 .2-.1 .3h-.3v-3.4h.3v.5l.2 .4a.15 .15 0 0 0 .2 0 .15 .15 0 0 0 0-.3l-.1-.2v-.4l.1-.2h.3h.2l1.1 1.2h.2l.1-1.4a.15 .15 0 0 0-.2-.1 .15 .15 0 0 0-.1 .1v.9l-.9-.9-.4-.1-.5 .1-.2 .4h-.3zM89 58.4h.2l.1 .1v.2l-.1 .2h-.2z"/>
<path d="M89.9 58.4h.2l.1 .1v.2l-.1 .2-.3-.2zM90.8 58.4h.3v.4h-.3zM93.1 58.4h.2l.1 .1h-.4zM88.7 57.8h5.5v1.3h-5.5v-1.2h.1l.1 1.1h.4l.2-.2v-.3h.2v.3l.3 .2 .3-.1 .1-.4h.2l.1 .4 .3 .1 .3-.2v-.3l-.2-.2 .4 .1v.4l.2 .2 .2-.1-.2-.1v-.4h.4v.2l.4 .1-.1 .2h-.3l.1 .1h.4v-.2v-.2l-.4-.1v-.1h.7v.4l.2 .2h.3v-.2a.26 .26 0 0 1-.4-.1l.5-.1-.1-.3-.3-.1-.2 .2h-.7h.4l-.1-.2h-.2l-.2 .2h-.4l.2-.1-.2-.1v-.3h2.1v.9l.2 .2 .1-.1-.2-.1v-.9h-2.2h-.1l-.1 .3-.1 .1-.6-.1-.2 .3h-.2l-.2-.2-.3-.1-.2 .3h-.2l-.2-.2-.3-.1v-.3h-.3zM122.9 41.6h.2l.1 .1-.4 .1zM124.5 41.6h.3v.1l-.3 .1zM122 41h3.8v1.4h-3.8v-.9h.1l.1 .8 .1-.1v-.5h.4v.4l.2 .2 .4-.1-.1-.1h-.3l-.1-.2 .5-.1v-.1h.3v.2l.4 .1-.1 .1h-.3l.1 .2 .3-.1 .1-.2v-.2l-.4-.1h.7v.4l.2 .2 .3-.1v-.1a.26 .26 0 0 1-.4-.2l.5-.1-.1-.3h.2l.2 .1v.6l.3 .1v-.2l-.2-.1v-.4l.3-.1-.3-.1v-.2l-.1-.1v.3h-.7l-.2 .3h-.7l.4-.1-.2-.2-.3 .1v.2h-.3l-.2-.3-.3 .1-.1 .2h-.4l.2-.1v-.1h-.5zM166.7 41.4h.7v.6a.39 .39 0 0 1-.4 .2 .39 .39 0 0 1-.3-.2zM165.2 37.2h2.7v9h-2.7v-1.5h.2v1.1a.15 .15 0 0 0 .2 .2 .15 .15 0 0 0 .1-.2v-.4l2-.1v-.1l-.6-.6a.15 .15 0 0 0-.2-.1 .15 .15 0 0 0 0 .2l.2 .4h-1.4v-.4a.15 .15 0 0 0-.1-.2 .15 .15 0 0 0-.2 .2h-.2v-3.5h.2l.1 .2h.9v.7l.2 .3 .3 .1h.3l.3-.1 .2-.4v-.8l-.1-.1h-2l-.2 .1h-.2v-2.1h.2l.9 .7-.8 .6a.15 .15 0 0 0-.1 .2 .15 .15 0 0 0 .2 0l1-.6 .9 .6a.15 .15 0 0 0 .2 0 .15 .15 0 0 0-.1-.2l-.8-.6 .8-.5a.15 .15 0 0 0 .1-.2 .15 .15 0 0 0-.2-.1l-.9 .6-1-.6-.2 .1h-.2v-1.6h.2v1a.15 .15 0 0 0 .2 .1 .15 .15 0 0 0 .1-.1v-.8h.8v.5a.15 .15 0 0 0 .1 .1 .15 .15 0 0 0 .2-.1v-.5h.6v.8a.15 .15 0 0 0 .2 .1 .15 .15 0 0 0 .1-.1l-.1-1.1h-2l-.2 .1h-.2zM19.8 62.8a.64 .64 0 0 1 .6 .8 .59 .59 0 0 1-.4 .7h-.2zM19 62h2.2v3h-2.2v-2.5h.3v2l.1 .2 .6 .1 .4-.2 .3-.3 .2-.6-.1-.8-.3-.5-.4-.1h-.6l-.2 .1v.1h-.3zM42.8 78.8a.39 .39 0 0 1 .6 .2v.6h-.8v-.6z"/>
<path d="M113.4 60.8h1.9v3h-1.9v-2.5h.2l.1 2.1 .1 .1h1a.25 .25 0 0 0 .3-.2 .25 .25 0 0 0-.3-.3h-.7v-.5h.4a.25 .25 0 0 0 .3-.3 .25 .25 0 0 0-.3-.2h-.4v-.5h.7a.25 .25 0 0 0 .3-.2 .25 .25 0 0 0-.3-.3h-1l-.2 .3h-.2zM135 64a.43 .43 0 0 1 .4 .4 .43 .43 0 0 1-.4 .4zM135.6 61.8a.42 .42 0 0 1 .4 .4 .42 .42 0 0 1-.4 .4zM136.1 64.1l.1 .4h-.2zM137 67.2a.42 .42 0 0 1 .5 .4 .42 .42 0 0 1-.5 .5zM137.3 61.9l.2-.1h.2a.57 .57 0 0 1-.1 .8h-.2a.7 .7 0 0 1-.1-.7zM137.7 64.1l.2 .4h-.3zM134.7 63.7h3.6v4.6h-3.6v-.7h.1l.1 .4 .3 .2 .4-.1-.1-.5-.3 .1 .2 .1v.2a.41 .41 0 0 1-.5-.4 .41 .41 0 0 1 .6-.4v-.1h.3l.1 1.1 .1-.1v-.7l.4 .8h.2v-1.1h.3v1.1l.5-.1 .2-.2v-.4l-.1-.3-.3-.1h-.3h-.4l-.1 .7-.5-.7h-.1h-.8l-.2 .5h-.1v-1.5l.5 .1v.3l.1 .1 .1-.4h.4l-.4-.2 .7 .1 .4-.1 .1 .1v.3h-.3h-.2h-.1l.2 .2h.3l.3-.2v-.3l-.3-.3h-.3v-.2l.7-.1 .3 1 .1 .1 .4-1.1h-.1l-.3 .8-.3-.9-.1 .1h-.8l-.1 .5h-.6v-.3h-.1l-.1 .4h-.5v-2.2h.1l.1 1.1 .5-.1 .4 .1 .1-.3h.4l.1 .2 .1 .1-.3-1.1 .6 .1 .1 1 .4-.1 .1 .1 .1-.3h.4l.1 .3 .1-.1-.3-1.1-.1 .1-.4 1h-.3v-.9h.3v-.1l-1.2-.1-.4 1.1h-.3l.2-.4-.1-.5-.3-.2-.5 .1zM133.6 61.5h6.4v1.4h-6.4v-1.2h.1v1l.1 .1 .6-.1-.1-.1h-.4v-.9h.6v1l.1 .1 .6-.1-.1-.1h-.4v-.4h.3v-.1h-.3v-.3l.5-.1h.2l.1 1.1h.3l.2-.2 .1-.6h1.1v.6l.3 .2h.2l.2-.2 .1-.2v-.4l-.2-.3h.5v.8l.2 .3h.2l.3-.3v-.8l.4 .1v.9l.1 .1 .1-1 .3-.1-.1-.1h-.9l-.1 .9-.1 .1h-.2l-.1-.1-.1-.9v.1l-.8-.1-.3 .2v.2h-1.1l-.1-.2-.2-.2-.4 .1-.3-.1-1.2 .1-.1-.1-.2 .1zM142.5 61.9l.1-.2 .2 .1a.57 .57 0 0 1 0 .8h-.2a.7 .7 0 0 1-.1-.7zM144.9 66.8a.42 .42 0 0 1 .4 .4 .42 .42 0 0 1-.4 .4zM145.3 61.7a.42 .42 0 0 1 .4 .5 .42 .42 0 0 1-.4 .4z"/>
<path d="M146 66.9l.1 .4h-.2zM146 63.5a.42 .42 0 0 1 .4 .5 .42 .42 0 0 1-.4 .4zM147 61.9l.1-.2 .3 .1a.57 .57 0 0 1-.1 .8h-.2a.7 .7 0 0 1-.1-.7zM143.6 63.3h4v6.2h-4v-1h.1l.2 .3 .4 .2-.1 .2h-.4v.1l.4 .1 .2-.2v-.3l-.3-.2h.6l.1 .5 .3 .2 .3-.1 .1-.1-.1-.1a.29 .29 0 0 1-.5-.1 .37 .37 0 0 1 0-.4 .37 .37 0 0 1 .4-.2h.1v-.1h.3l.1 1.1 .6-.1-.1-.1h-.4l-.1-1-.1 .1h-.8l-.2 .4h-.6l-.2-.1v-.1l.1-.1h.5l-.2-.2h-.3l-.3 .3h-.1v-1.6h.1l.2 .3 .4 .2-.1 .2h-.4v.1l.4 .1 .3-.3-.2-.3-.4-.2v-.1l.1-.1h.4v-.1h.3l.1 1.1 .5-.1 .4 .1 .1-.3h.4l.1 .2h.1l-.4-1.1-.1 .1-.3 1h-.3l.1-.2 .1-.4-.3-.4-1.2-.1-.3 .3h-.1v-1.2l.6 .1v.4l.1-.1v-.3l.4-.1-.1-.1h-.3v-.4l-.1 .1v.3l-.6 .1v-.6l1.9 .1-.3 .3 .3 .1 .1 .3-.2 .1-.4-.1-.1 .1 .2 .2h.4l.1-.2 .1-.4-.2-.2 .2-.3h.1l.4 1.1 .5-1.1 .1 .1h.5l-.3 .3 .3 .1v.3l-.6 .1 .2 .2h.3l.3-.3v-.3l-.2-.2 .2-.3-1-.1-.3 .8-.3-.8-.1 .1-.2-.1-2 .1v-1.2h.1l.2 .5 .2 .1 .4-.1v-.4h-.3v.1h.2v.2l-.2 .1a.43 .43 0 0 1-.3-.5 .43 .43 0 0 1 .5-.3v-.1h.4v1h.1v-.7l.5 .7h.1v-1h.3l.1 1h.4l.2-.2 .1-.4-.3-.5h-.9v.8l-.5-.8-.1 .1-.8-.1-.3 .5h-.1zM142.2 61.5h7.4v1.4h-7.4v-.9h.1v.5l.2 .2h.3l.2-.1 .1-.6-.1-.3h.4v1h.1h.5v-.1h-.5v-.9h.7v1h.1h.5v-.1h-.5v-.4h.4l-.1-.1h-.3v-.4h.5h.3l.1 1h.2l.3-.1 .1-.6h1l.1 .6 .2 .1h.3l.2-.1v-.3v-.3l-.1-.3h.4v.8l.2 .2h.3l.2-.2v-.8h.5v1h.1l.1-1h.2v-.1h-1v.9l-.1 .1h-.2l-.1-.1-.1-.9-.1 .1-.8-.1-.2 .2-.1 .2h-1l-.1-.2-.3-.2-2.4 .1-.4-.1-.2 .2-.1 .2h-.1zM189.5 60.9h1.9v3h-1.9v-2.5h.3v2a.25 .25 0 0 0 .2 .2 .25 .25 0 0 0 .3-.2v-.8h.4a.25 .25 0 0 0 .2-.3 .25 .25 0 0 0-.2-.2h-.4v-.5h.7a.25 .25 0 0 0 .2-.2 .25 .25 0 0 0-.2-.3h-1l-.2 .3h-.3zM42.7 86.1a1.29 1.29 0 0 1 1.6 0v.2v.4a1.29 1.29 0 0 1-1.6 0l-.1-.1zM42.1 78.3h2.8v9.2h-2.8v-1.3h.2l.1 .5 .3 .4 .4 .1 .7 .1 .5-.2 .3-.4v-.5l-.1-.2-.2-.3-.4-.1h-.7l-.5 .1-.4 .5h-.2v-2.5h.3l.1 .2 1.7 .1 .1 .2v.3l-.2 .3h-1.6a.15 .15 0 0 0-.2 .1 .15 .15 0 0 0 .2 .2l1.7-.1 .3-.2 .1-.2v-.5l-.1-.2-.4-.3h-1.6l-.1 .1h-.3v-1.7h.2v1.1a.15 .15 0 0 0 .2 .2 .15 .15 0 0 0 .1-.2v-.4h1.9a.15 .15 0 0 0 .1-.2 .15 .15 0 0 0-.1-.1h-1.9v-.4a.15 .15 0 0 0-.1-.2 .15 .15 0 0 0-.2 .2h-.2v-3h.2l.1 .8 .1 .1h2a.15 .15 0 0 0 .1-.1 .15 .15 0 0 0-.1-.2h-.8v-.2l.9-.7a.15 .15 0 0 0 0-.2 .15 .15 0 0 0-.2 0l-.7 .5-.3-.4-.2-.1h-.3l-.4 .2-.2 .3h-.2zM130 99.9l.7-.6h.2l-.4 .3-.6 .4zM130.6 98h.4l.4 .2zM134.7 95.9l.1 .1zM136 95.6l.1-.1z"/>
<path d="M136.3 95.4h.2l-.3 .1zM135.1 95.8l1.5-.8h.5l.3 .2h-.1a2.11 2.11 0 0 0-1.5 .3zM137.9 99.1l.2 .3 .1 1.2 .2-.2 .1 .3h-.3l-.2 .6zM137.8 98.9l.3-.2 .3 .2-.3-.1-.3 .2zM138.3 93.5l.2 .1a1.47 1.47 0 0 1 .3 1.8l-.1-.1 .1-.3v-.6l-.4-.7-.4 .7 .1 .9a.99 .99 0 0 1-.1-1.3zM138.3 99.7h.1l.1 .3-.2-.3v.2zM127.7 99.6l.4-.3 .5-.2 1.3-.2 1 .1-.7-.2-1.3-.2h.2l.7-.1 1.2 .3 .1-.1-.9-.2 1 .1-.9-.3-.8 .1 .1-.1a2.35 2.35 0 0 1 1.6 .1l.3-.2 .1-.2-.6-.1-.7 .1 .1-.2a1.19 1.19 0 0 1 1.3 .2h.1a9.5 9.5 0 0 1 6-2.5l-.5-.6-.5-.1-.7 .3-1.1 .7 1.2-.9 .7-.2 .6 .1v-.3h.1a.86 .86 0 0 0 .4 1h.9l.3-.5-.1-.9-.7-1a2.42 2.42 0 0 0-.8 1.4h-.1v-.1l-1.1 .3a10.4 10.4 0 0 0-2.5 1.7l-.9 .4h-.4a.55 .55 0 0 1-.4-.5h.3v.3l.3 .1 .4-.1 .1-.2-.1-.3-.4-.1-.2 .1-.1 .2h-.3a.65 .65 0 0 1 .7-.5 .65 .65 0 0 1 .6 .6l.4-.2-.3-.4v.1l-.8-.2-.3 .1-.4 .3v.5l.2 .3 .4 .1-.1 .1h-.3a.79 .79 0 0 1-.3-1 .79 .79 0 0 1 .9-.5l.6 .2-.3-.3h-.6l-.4 .2-.3 .2-.1 .4v.5l.5 .6-.3-.2a1.1 1.1 0 0 1-.1-1.4 1.1 1.1 0 0 1 1.5-.3l.4 .3 .3 .2 .2-.1a8.4 8.4 0 0 1 3.1-1.7l1-1.4 .9 1.3 1.1 .4a10 10 0 0 1 2.4 1.5l.2-.2a1.2 1.2 0 0 1 1.5-.4 1.2 1.2 0 0 1 .7 1.5l-.3 .3-.4 .2 .2-.1a1 1 0 0 0 .2-1.5 1 1 0 0 0-1.4-.2l-.6 .5 .2 .3-1.2-.9-1.6-.9-1-.3v.6a.67 .67 0 0 1 1-.1l.8 .4-1.3-.4-.3 .1-.4 .4a.12 .12 0 0 0-.1 .2 .12 .12 0 0 0 .2 0 9.2 9.2 0 0 1 5.8 2.5h.2a1.21 1.21 0 0 1 1.4-.1l-.8-.1-.6 .3 .4 .3a2.9 2.9 0 0 1 1.7-.1l-1.7 .2v.1h.1h.6l-.6 .2-1-1-.8-.5a10 10 0 0 0-11.9 .7l-1 1.1h-1.3l.9 .2-.3 .2a9 9 0 0 0-2.8 5 10.3 10.3 0 0 0 2.5 9.7l.4 .2-1.7 .1-1-.2a3.2 3.2 0 0 0 2.7 .3l.5-.1v.1a3.2 3.2 0 0 1-3.3-.2l-.1-.1a.6 .6 0 0 1-.1-.9 .6 .6 0 0 1 .8-.1l.3 .4 .1 .4 .5 .1-.4-.5a14.1 14.1 0 0 1-2-4.7l-.3-.4-1.3-.8 1.1 .6a1.29 1.29 0 0 1 .7 .8 9.7 9.7 0 0 0 2.5 5l.2 .1h-.1a2.02 2.02 0 0 1-1.9-.5l.1-.3 .2-.1-.1 .4 .5 .3a.12 .12 0 0 0 .2 0 .12 .12 0 0 0-.1-.2 .65 .65 0 0 0-.5-.6l-.2 .1-.2 .2a.6 .6 0 0 0 .7 .7l1 .1h.8l-.1-.1a7.9 7.9 0 0 1-2.4-4.1 10.9 10.9 0 0 1 2.5-10.7l-1.1 .1a1.76 1.76 0 0 0-1.1 .3h-.1l.2-.2 .4-.2 2-.2a3.7 3.7 0 0 0-2.2 .2l-.5 .4-.1 .6 .1 .2h.3l.2-.1 .2-.3 .1-.3-.4 .1-.3 .4v-.3a1.24 1.24 0 0 1 1.2-.4l.6-.1a10.9 10.9 0 0 0-2.5 5.1l-.2 .4-.8 .4 .6-.5 .2-.3a11.2 11.2 0 0 1 2.2-4.8l.1-.1-.5 .1-.2 .5-.5 .6a8.9 8.9 0 0 0-1.2 3.3 5.8 5.8 0 0 1-1.7 2l-.6 .7 .8 .9a3.1 3.1 0 0 1 1.1 2.2l.1-.3v.5l-.1 .2h-.1l-.2-.2-.2-.5a3.6 3.6 0 0 0-.6-1.7l.2 .1a3.6 3.6 0 0 1 .6 1.8l.1 .3 .1 .1 .1-.2-.5-1.5-.4-.6h-.2l-.9-1-.1-.2a5.1 5.1 0 0 0 1.8-3.4 .31 .31 0 0 1 .4-.2 .31 .31 0 0 1 .1 .4l-.1 .4v-.4a.21 .21 0 0 0-.3-.3 .21 .21 0 0 0-.1 .4 6.2 6.2 0 0 1-.7 2.1l.8-.9a2.57 2.57 0 0 0 .6-1.3 6.7 6.7 0 0 1 1.2-2.9l-.5-.3a.83 .83 0 0 1 .3-1zM131.9 98.3l.2-.2h.6l.2 .4h.2v.2h.1l.1 .5 .2-.2-.6-.9 .3 .1v-.2l-1.1 .1 .3-.2h.7l-.1-.1-.6 .1 .2-.2h.5l.4 .5 .3 .6 .6-.4-.2-.6h-.1v-.2l-.1-.3-.2 .1 .5 .9-.1 .1-.2-.1 .1 .2-.1 .1-.2-.1 .1-.2-.2-.2-.1 .1-.3-.4h.2l.1 .2v-.2l-.3-.1h.4l.1 .2v-.2h-.5h.2l-.1-.1-.3 .1h-.5l.2-.2 .8 .1v-.1h-.8l.7-.4h.8l.5 1 .4-.1-.1-.3h.2h-.2l-.1-.2-.1 .1 .1 .3-.1 .1-.2-.4 .3-.2-.1-.1-.2 .2-.2-.3 .3-.2-.1 .3h.1l.1-.1-.1-.3-.5 .2h-.8l.6-.3h1l.4 1 .5-.1h5l.3 .1-.1-.2 .1-.2h.3v-.1l-.3 .1 .1-.1v-.2l.2-.4-.4-.1 .1 .3-.3 .8h-5v-.1h.4h4l.3 .1-.1-.2 .1-.3 .1-.1-.1-.2 .3 .1 .1-.2-.1 .1h-.3l.1-.2 .2 .1 .1-.2-.3 .1v-.2h-.2l-.1 .8-.1 .3h-4l-.1-.1-.6 .2-.2-.3 .2-.2h-.1l-.1-.2h.6v.4h.2l-.1-.5-.1 .1h-.6l.1-.3h.2v-.1l-.7 .2h-1l.9-.4h1.7l.2 1.1 .3-.1h-.2l2.5 .1v-.2h.1l.1 .2h.5l.1-.9 .2-.1-.1-.1h-.3l.1 .3-.2 .8h-.2l-.1-.2h-.2l.2-.2-.2-.2h.3l-.2-.2v-.2l.1-.1v.3l.1-.3-.1-.1h-.2l-.1 1.1h-2l-.1-.1v.1l-.3-.1v-.2h.1l.1 .1v-.1v-.1l-.1 .1h-.1v-.2l.1-.1-.1-.1-.1-.2 .2-.2-.4 .1h-1.7l.4-.1h2l.1 .2 .1 .9 .5-.1h-.3l-.1-.1v-.3l.2-.2-.2 .1v-.5l.1 .2 .1-.2h.3l.1 1h.2l-.1-.1 .1-.2-.2-.1 .2-.1-.1-.3 .2-.3-3.2 .1a9.6 9.6 0 0 1 10.2 2.7l.3 .6-.4 .5-.1 .5 .4 .8a.65 .65 0 0 0-.6-.3l-.9-.1-.3-.1a4.4 4.4 0 0 0-3.3-2.5 7.5 7.5 0 0 0-7.1 1.4l-.6 .9a.69 .69 0 0 1-.7 .4l-.8 .1-.4 .4 .2-.7h1a.73 .73 0 0 0 .8-.6 5.5 5.5 0 0 1 4.2-2.3 7.2 7.2 0 0 1 6.1 1.7l.8 1.2h1.3l-.1-.2-.5 .1-.5-.1-.4-.5h.1l.3 .4-.2-.3 .3 .1h.3v-.1l-.3 .1-.5-.2-.3-.3h.4l.2 .2h.2l.1 .2v-.3l.2 .1-.2-.2 .1-.2 .1 .2 .1-.2-.1-.1 .3-.7-.2 .1-.6 .9h-.6l-.1-.2h.4v.1h.1l.7-1.1v-.1l-.7 1.1h-.5l-.3-.3h.4l.2 .2 .7-1.1-.1-.2h-.1l-.6 1.1h-.5l-.2-.2h.4l.2 .1-.2-.2-.4 .1-.4-.3h.6l.2 .2 .1-.2h.4v-.1l-.1 .1h-.3l.1-.2h.2l.1-.1-.3 .1 .1-.1h.4l-.1-.1v.1h-.3l.1-.3 .2 .1 .1-.2v-.1l-.1 .2h-.2l.1-.2v-.1l-.7 .9h-.6l-.4-.2h.7l.1 .1 .1-.3-.2 .2h-.7l-.4-.2h.8l.1 .1 .2-.2h.4v-.1l-.1 .1h-.3l.1-.2h.3l.3-.3-.1-.1-.1-.1-.1 .5h-.3l.3-.5-.2-.2-.5 1h-.8l-.8-.3h1.1l.3 .2v-.2l.2 .1v-.1h-.2l.2-.2 .1-.1h-.1l.2-.5-.2-.1v.4l-.3 .4h-.1l.3-.8h.1l-.1-.1-.2-.1-.2 1.1h-1.1l-1.2-.3h1.7l.4 .2-.2-.3 .1-.1h.2v-.1l-.2 .1 .3-.7-.3-.1-.3 1h-2h1.8l.1-.3-.2 .3h-1.8a7 7 0 0 0-6.4 1.9l-.5 .8-.5 .2h-.5l-.1 .1h-.2l.1-.4-.1-.2h1v-.1l-.1 .1h-.9l-.4-.5h-.1l.2 .3h-.3h.4l.1 .3-.7-.1-.3-.2v-.1l.6-.3h1.3l.3 .4 .1-.1-.2-.5-.2 .2h-1.3l.4-.7h.5l.4 .5h.1v-.2h.2l.2 .5 .1-.1-.3-.4h-.2l-.3-.2 .4 .1v-.1l-.4-.1 .1-.1h.2l-.1-.1h-.3l-.1 .2h-.5l.4-.4h.5l.5 .7 .3 .2-.5-.8h.1l.5 .7 .1-.1-.3-.3h.2h.1v-.1h-.4l.1-.2h-.4v-.2l.2 .1-.2-.2-.3 .2h-.5zM138.9 99.1l.1 .1-.2 2-.1-.4zM138.5 98.9l.5-.1 .2 .2zM139.6 95.4l.2-.1zM139.5 95.1h.5z"/>
<path d="M140.2 95.1l.4 .1zM140.7 95.3l.3 .2zM141.2 95.6l.2 .1zM141.3 95.3l.8 .7zM143.3 96l.6-.4 .7 .1h-.1a1.49 1.49 0 0 0-1.3 .3zM143.5 96.1a.64 .64 0 0 1 .7-.4 .64 .64 0 0 1 .5 .6l-.3 .4-.5 .2 .5-.3 .2-.3a.46 .46 0 0 0-.6-.4 .46 .46 0 0 0-.3 .6v.2l.1 .1-.4-.3-.1-.1 .3 .1 .1-.4-.1 .1-.1 .2h-.2zM145 96.1v.4l-.2 .4a.38 .38 0 0 1-.4 .3 .38 .38 0 0 1-.3-.2h.3a1.09 1.09 0 0 0 .6-.9zM145.9 99.8h.2l.6 .3-.3 .1-.7 .2 .1-.2 .7-.1-.4-.2 .1 .2h-.4zM146.3 99.6l.3 .1 .1 .2zM145.9 99.2l.9-.2-.7 .3zM146.8 99.7h.2l.2 .1a11 11 0 0 1-.2 14.6l1.6-.1 .6-.2-.4 .3-.5 .1-1.6-.1 .1-.1a10.6 10.6 0 0 0 2.1-11.5 9.4 9.4 0 0 0-2-3.1zM146.5 99.5h1.9l.5 .1 .2 .3-.6-.3z"/>
<path d="M147.4 99.7l1.5 .2 .3 .3 .1 .3-.5-.5-1-.2v.1a12.4 12.4 0 0 1 2.3 5.2l-.1-.1a11.3 11.3 0 0 0-2.5-5.1zM145.7 98.9l1.5-.3h.7l-2.1 .4zM146.2 99.4l.4-.2a2.43 2.43 0 0 1 2.9 .7 .56 .56 0 0 1-.2 .9 .56 .56 0 0 1-.8-.4l-.2-.4 .1 .1 .2 .4 .3 .2h.3l.2-.3a1.09 1.09 0 0 0-1.2-1.1h-1.5l-.4 .2zM166.3 85h.8v.6a.39 .39 0 0 1-.4 .2 .39 .39 0 0 1-.4-.2zM164.9 79.9h2.7v6.5h-2.7v-.4h.2l.2 .1 .7-.5 .3 .4 .3 .1 .5-.1 .3-.4-.1-.9h-2.1a.15 .15 0 0 0-.1 .1 .15 .15 0 0 0 .1 .2h.8v.2l-.9 .8h-.2v-3.7h.2l.1 .2h2a.15 .15 0 0 0 .2-.1 .15 .15 0 0 0-.2-.2h-1.4l1.5-.9 .1-.1-.1-.1h-2.1a.15 .15 0 0 0-.1 .1 .15 .15 0 0 0 .1 .2h1.5l-1.6 .9h-.2v-2.1h.2l.1 .2h2a.15 .15 0 0 0 .2-.1 .15 .15 0 0 0-.2-.2h-2l-.1 .1h-.2zM19.9 115.3l.1 .4h-.3zM18.7 114h2.3v3h-2.3v-.5h.3a.25 .25 0 0 0 .1 .2 .25 .25 0 0 0 .3-.1l.2-.4h.6l.1 .4a.25 .25 0 0 0 .3 .1 .25 .25 0 0 0 .2-.3l-.7-2-.3-.1-.2 .1-.6 2.1h-.3zM42.9 106.2a1.4 1.4 0 0 1 1.4 .1l.1 .2-.1 .4a1.29 1.29 0 0 1-1.6 0v-.4zM42.2 98.6h2.7v9.1h-2.7v-1.3h.2v.5l.3 .4 .5 .1 .7 .1 .4-.2 .4-.4v-.5l-.1-.2-.3-.3-.4-.1h-.7l-.4 .1-.4 .5h-.2v-2.5h.2l.1 .2 1.8 .1 .1 .2v.3l-.3 .3h-1.6a.15 .15 0 0 0-.1 .1 .15 .15 0 0 0 .1 .2l1.7-.1 .4-.2 .1-.2v-.5l-.2-.2-.3-.3h-1.7l-.1 .1h-.2v-1.7h.2v1.1a.15 .15 0 0 0 .1 .2 .15 .15 0 0 0 .2-.2v-.4h1.8a.15 .15 0 0 0 .2-.2 .15 .15 0 0 0-.2-.1h-1.8v-.4a.15 .15 0 0 0-.2-.2 .15 .15 0 0 0-.1 .2h-.2v-2.3h.2l.1 .2h2.1l.1-.1v-1a.15 .15 0 0 0-.2-.1 .15 .15 0 0 0-.1 .1v.8h-1.9l-.1 .1h-.2zM95.1 113.4l.4 .1 .1 .1v.2l-.5 .1zM95.1 114.4h.5l.1 .1v.3l-.2 .1h-.4zM94.3 112.7h2.2v3h-2.2v-2.5h.3v2l.1 .2h1l.4-.3 .1-.3v-.4l-.2-.3 .1-.6-.1-.3-.5-.3h-.7l-.2 .3h-.3z"/>
<path d="M124.8 106.9l.3-.1v.4l.2 .2-.6-.3h.3v-.1l-.3 .1zM125.8 108.4h.1a2.36 2.36 0 0 1 .8 1.4 10.7 10.7 0 0 0 1 2.9l.2 .4-.3-.3a16.1 16.1 0 0 1-1.2-3.4zM126.2 103.7l.1 .1a3 3 0 0 1-.6 1.7zM125.4 106.6l1.2-.7-.2 .2-.9 .5-.1 .3 .1 .5 .9 .5 .1-1.7v1.8l-1.1-.6-.1-.5zM124.8 107.3l1.4 .7 .5 .4v-2.3l.1-.3v2.8zM125 106.5l1.9-1.2-.1 .1-.3 .3-1.6 .9zM127.4 107.2a6.3 6.3 0 0 0 1.5 2.4v.1a4 4 0 0 1-1.3-1.6zM127.4 106.8l.4-.2-.4 .3zM127.9 106.6h.3zM128.3 106.6h.5l.7 .6-.7-.5zM128.5 108.6l.4 .3-.1-.2 .2-.1 .1 .5zM129 109.9l.3 .3h.3l-.1 .2 .2 .1-.4 .3-.2-.1-.1 .1v-.3h.4h-.4l-.2-.1h.5l.1-.1-.6 .1v-.1h.4z"/>
<path d="M129.1 108.4v.2zM129.2 107.5l-.1 .2zM129.3 108.4l.1 .3-.2 .3zM129.3 107.4l.2-.1zM129.6 107.2l1.1 .1h-.9zM129.6 109.4l.2 .1h-.1zM129.6 110.8l.2-.1-.1 .4zM129.7 111.7l.1 .4zM129.8 108l1.2 .4 .2 .2v.2l-.3-.3-.3-.1-.1 .1 .1 .3-.7-.6 .3 .1-.3-.1zM130 112.3l.3 .3 .4 .1-.4-.1zM129.9 108.4l.3 .2zM129.6 106.5l.2-.1-.1 .2 .2 .2-.1-.2 .4-.2 .1 .2-.2-.1-.1 .2 .6 .2-.5-.1-.1 .1 .6 .1 .8 .1v-.2l.1 .2-.1 .2-.2-.1-1.2-.2-.3-.2z"/>
<path d="M128.6 109.1l.4 .3 1.1-.4 .7 .3h-.2a1.56 1.56 0 0 0-1.3 .1l-.2 .1 .2 .1h-.2zM130.2 107.7l.1 .1zM130.2 114.1l.4 .1 .2 .1h-.2zM130.1 113.6h.5l.3 .1 .4 .4a1.58 1.58 0 0 1-1.2-.5zM129.8 102.5l.4-.2h.4l-.5 .1-.4 .3zM130.4 112.2l.3 .2h-.2zM130.4 109.4l.8 .3 .3 .3zM130.4 100.5h.3zM130.2 110.9l.4-.2 .1 .1-.2 .2 .2-.1-.2 .3-.4 .2v-.4l.2 .1 .2-.3-.4 .2zM130.6 111.4l.1-.1 .1 .7 .2 .2 .3-.4 .2-.2 .6 .1 .2 .2-.5-.1-.5 .2-.2 .4-.4-.4-.1-.5zM130.6 106.5l.6 .3-.5-.2zM130.7 108.9l.4 .2 .4 .2 .6 .5 .3 .5-1-.9 1 1.1-1.6-1.4z"/>
<path d="M130.8 112.6l.2 .1h-.2zM130.8 106.3h.3l.1 .2zM130.4 102.6a.92 .92 0 0 1 1.2 .1l-1.3 .1zM129.1 115.3l.9-.2h1l.2 .1 .3 .2a11.8 11.8 0 0 0 13.8 .1l.3-.3 .1 .1a8.6 8.6 0 0 1-4.9 2.3l-1.9 .3 .5 .8 .2 .2h.4l.6-.3-.3 .3-.4 .1h-.3l-.2-.2-.6-.9h-.6l-.2 .1a1.98 1.98 0 0 0-.1 2.3l.5 .7 .7-1.1 .2-1v.1l-.1 .8 1.1-.5a8.6 8.6 0 0 0 2.7-1.9l.2-.1-.3 .4 .1 .2a1.14 1.14 0 0 0 1.2 .5 1.14 1.14 0 0 0 .9-1l-.3-.4-.4-.3 .4 .1 .3 .4 .1 .4-.2 .5a1.54 1.54 0 0 1-2.3-.2l-.4 .3a6.5 6.5 0 0 1-2.5 1.4l-.3 .2a3.5 3.5 0 0 0-1 1.3l-.1 .1-.1-.2a2.7 2.7 0 0 0-1.2-1.3 11.1 11.1 0 0 1-2.9-1.7h-.1a1.37 1.37 0 0 1-1.3 .6 1.37 1.37 0 0 1-1.1-1l.1-.4 .2-.4 .3-.2 .4 .1-.6 .2-.3 .4a.95 .95 0 0 0 1.3 1.1 1.09 1.09 0 0 0 .9-.6l-.4-.6 .2 .1a8.5 8.5 0 0 0 3.6 2.3l.1 .1v-.7l-.2 .1a1.28 1.28 0 0 1-1.6-.4l-1.5-1.4 .4 .3 .8 .7a1.75 1.75 0 0 0 1.3 .8l.8-.3v-.3l-.2-.1h.2l.4-.5a12.8 12.8 0 0 1-5.5-1.6l-1.4-1.1zM129.9 115.6l1-.2 .3 .1zM130.2 101l.8-.2-.4 .5v-.3l-.3 .3 .1-.2h-.2v.5l.3 .5h-.2l-.4 .1a1.24 1.24 0 0 0-.5 1.2v-.1a1.13 1.13 0 0 1 .9-1.3l-.2-.5zM130.7 107.5l.2-.1h.4l-.3 .6 .2-.5-.1-.1-.4 .2-.2 .5-.1-.2zM131.1 105.4l.1 .1 .1 .8zM131.1 100.6h.2l-.1 .1zM130.8 110.3l.3-.2 .5 .1 1 .7-.7-.4-.4-.1-.5 .2-.1 .1 .1 .1 .3-.1 .1 .1-.6 .1-.2-.4h.3l.1-.2h.6h-.6l-.2 .2h-.2zM129.8 115l1.1-.3 .4-.2v.2l-.2 .1 .2-.1v.2l-1.6 .1zM131 111.3h.4z"/>
<path d="M131.3 108.9l.1 .2zM131.3 110.5l.5 .1zM131.4 105.6l.1 .2 .1 .3zM130.3 115.9l1.2-.1a1.42 1.42 0 0 1-1.2 .1zM131.5 106.5l.2 .3zM131.2 101.9h.2h.2v-.1l.1 .1 .1 .1h-.2l.1 .4h-.2a.34 .34 0 0 1-.3-.4zM131.4 112.1l.3-.1h.3l.6 .7 .2-.3-.1 .4 .1 .1-.1 .2h-.3l-1-.1-.1-.2 .5 .2h.8l-.5-.8-.3-.1-.5 .2-.1 .6a1.22 1.22 0 0 0 1.5 .4h.2l.3 .4 .6 .3 1-.8-.3 .4-.6 .5a10.7 10.7 0 0 0 9.9-.4l.2-.3v.1a2.2 2.2 0 0 1-1.4 .9 11.1 11.1 0 0 1-9.7-.8l-.3-.2 .1 .4a11.9 11.9 0 0 0 8 1.4h1.8l.3 .7-.1 .1 .4 .2 .2-.2 .2 .1v-.1h-.2l.1-.1-.2-.1v.3h-.1l-.3-1-.3 .1h-1.8l1.3-.3h1.1l.5 1h.2l.4-.1v-.2l-.1 .1-.2-.2v.3l-.2-.1-.3-.7 .1-.3-.4 .2h-1.1l.5-.2h1l.1 .1 .1-.1 .1 .5 .1 .1-.1-.3v-.4l-.3 .1h-1l.5-.2h.9l.4 1.2h.1l.3-.3-.2-.1v-.3h.4h-.4l-.1-.2 .1 .6h-.1l-.2-1.1-.3 .2h-.9l.7-.3h.5l.1 .4 .2 .1-.2-.5h-.6l.4-.2h.2h.2l.1 .1-.1-.2-.4 .1 .1-.1 .1-.3 .4-.1h-.4l-.1-.1 1.1-.1 .2-.1 .3-.5v.2a3.2 3.2 0 0 0-.3 2.2l-.1 .1a8.1 8.1 0 0 1-3.1 1.6l-.9 .3a11.6 11.6 0 0 1-7-.3h1.1l.9 .2 .1-.1h.1l.3 .2h1.3l.1-.1-.1-.4-.1 .4a.16 .16 0 0 1-.2 0 .16 .16 0 0 1 0-.2v-.5l.4 .1-.1-.2-.1 .1h-.2l.1-.4h.3l.1 .1 .1-.1h.7l.1 1.2 .8-.1 .1-.1 .4 .1-.1-.3h.3v.2h.2l.8-.2-.1-.1h-.1l-.1-.1-.1 .1-.1-.2h.5l-.1-.1-.4 .1-.1-.4h.2v-.1l.2 .1 .1-.1-.5 .1v-.4h-.2l-.1 .1 .3 1-.2 .1-.1-.2-.1 .1h-.3v.2h-.3v-.3l.1-.2h-.2l.1-.1-.1-.1v-.3l.2-.1h-.4l.1 1.1-.1 .1-.1-.2-.2 .2-.1-.1-.1-.4h.3l.1-.1-.4 .1-.1-.6h.3l.1 .1v-.2l-1.2 .1-.1-.1-.4 .1 .1-.1h-.1a.18 .18 0 0 0-.2 .1 .18 .18 0 0 0 0 .2l-.1 1h-.4l-.1-.2 .1-1-.3-.1h-.2l-.2 1.1-.3-.1 .2-.2-.2-.3-.2 .6h-.1v-.1l-.2-.1 .1-1h.4v.4l.1 .1 .1-.4 .2 .1v-.1l-.1-.1-.4-.1-.3 .1 .1-.2h-.1l-.4 1.3a4.5 4.5 0 0 1-2.8-.7l-1-.7h.6l1.8 .9h.2l.2 .2 .9 .3v-.2l-.3-.1 .2-1h6.3l.3 .9v.2l.3-.1h.1l.2-.1 .2-.1-.1-.1-.1 .1h-.1l-.3-.8h.4v-.1l-.4 .1-.1-.2v.2l.1 .4v.2h.1l.1 .3h-.1l-.2-.3v-.3l-.2-.4-.2 .1h-6.3l-.6-.3-.3 1.1h-.2l-.4-.2 .3-1.1h-.2l-.2 1-.3-.2 .3-.7a.34 .34 0 0 0-.1-.4 .34 .34 0 0 0-.3-.1l-.4 1-.3-.2 .1-.2h.3h-.3l.1-.2 .2 .1-.2-.2 .3-.4-.2-.2-.3 .7-.3 .4h-.6l-.3-.2 .1-1 1.1 .1 .1-.2-.1 .1h-1.1l-.2-.7 1.2 .1-1.2-.1-.2-.6 .1-.5zM131.6 105l.1-.1-.1 .3zM131.7 112.6h.2l-.1 .1 .1 .2-.3-.1zM131.8 111.8l.6 .2 .2 .3v.2l-.3-.4zM132 102.4h.2zM131.9 102.9h.2l.1 .1z"/>
<path d="M129 103.8l.3-.2h.4l.1-.2-.1 .2h-.2l.3-.4a1.15 1.15 0 0 1 .7 .7h.1l-.1-.2h.3h.1h-.4l-.2-.3 .4 .1-.4-.1-.1-.1h.5l.2 .2 .2 .4-.1 .3 .4-.2 .2 .2v.3l.2-.2a1.88 1.88 0 0 0 .3-1.2l.1 .8 .3 .1 .2 .2a4.7 4.7 0 0 1-.5 2v.1l1.6-1.8 .9-.6 .1 .1-.1 .1-.8 .5-.8 .9 .4-.3h.7l.2 .2h.1l-.1-.1 .4 .1 .1-.2-.2 .1-.1-.1-.2 .1-.1-.1h-.1h-.7h.2h.4v-.1l-.4 .1h.3l-.1-.2 .2-.2 .3 .1-.3 .1 .2 .1 .6-.1h-.5l.1-.3v-.1l.2 .1-.1 .2 .1 .1 .5-.3-.4 .1 .1-.2-.1-.1 .6 .1v-.1l-.1-.2 .2 .1 .1-.1-.2-.2v.2l-.1-.1h-.1l-.1-.4h-.2l.2-.1 .2 .4 .1-.2h.1l.3 .6 .1-.1v.3l-.3 .3h-.1l.3-.4-.2-.1-.5 .4v.1l.2-.1-.2 .1 .1 .2-.2 .1 .2 .2-.3 .2-.4 .1-.4-.2-.1-.2 .6 .3 .2-.1h-.4l-.1-.1h.6l.1-.1-.7 .1-.5-.3-.7 .4-.4 .3a5.8 5.8 0 0 0-1.3 2.9l-.1-.1a4 4 0 0 1 .7-2.2v-.2l-.2-.4-.7-.6v-.2h.2l.5 .5 .3 .7 .3-.9 .2-1.2-.3-.2-1 1.1h-.2l.1-.2v-.1l-.4 .4-.4 .2-.3-.1-.4-.3h.1l.3 .2 .4-.1h.1h-.2v-.1h.5l.1-.3h.2l.1-.1h-.2h-.1v-.3l-.1 .3 .1 .2-.2 .2h-.4l-.1-.1-.1 .2-.3-.2-.2 .1v-.3l.2 .1 .1-.1h-.3l.1-.1 .3-.1-.3 .1 .1-.2-.2-.2h.2l.1 .2 .4 .2-.1 .1h.2l-.1 .2 .3-.2-.1 .2h.1l.1-.1-.1-.1 .2-.4-.1-.1h.1l.1-.2v-.1l-.2-.1 .1 .2-.2 .2v.2l-.2-.2-.4 .1-.2-.1h-.2v-.2h.1l.1-.2h.2l.2 .2-.1-.2h-.3l.1-.4-.2 .6-.3-.1 .1 .2h-.1l.1 .4-.1 .1v.4h-.2l.1 .2v.1h.1l-.2 .3 .2-.2 .2 .1v-.2l.2 .1-.2 .2h.3l-.1-.2 .3 .1-.1 .1 .2 .1v-.2l.2 .1h.1l-.2 .3h.1l.3-.4h.1v.2l-.3 .3-.4 .1h-.5l-.1-.2-.1-.2h.6h-.6v.5l-.7-.2h.5h-.9l-.6 .2 .7-.3h.6l-.2-.1-.4 .1 .3-.2 .5 .1-.1-.1h-.4h.2v-.1l-.2 .1 .5-.4-.6 .1-.2-.2h.3h-.3v-.1h.3l.3 .1-.2-.2-.5 .1 .1-.3 .2-.3 .2 .4 .4 .3-.3-.4-.1-.7h.3l.2 .3-.1-.3h-.4zM132.1 104.3l.1 .1-.4 1 .1-.7zM131.5 102.9l.5-.3 .3 .1-.5 .1-.5 .8 .3-.6-.4 .6zM131.2 111.1l.9-.2 .5 .1a.7 .7 0 0 1 .6 .7v.8a.4 .4 0 0 1-.2 .5v-.1a1.44 1.44 0 0 0-.3-1.8h-.2l.2 .1a1.59 1.59 0 0 1 .2 1.7v-.9l-.3-.3 .4 .1-.1-.1-.8-.2-.1-.3 .5 .1 .1 .1-.3-.1v.1l.2 .1 .1-.1 .2 .2-.1-.2-.3-.2h-.5l.1 .1-.1 .1-.3-.2zM132.3 101.6h.1l-.1 .2zM132.1 117l.4-.1-.4 .4v.5a.84 .84 0 0 0 .8 .4 .84 .84 0 0 0 .7-.6l-.3-.4-.4-.1-.3 .2-.1 .4 .2 .2h.4l.2-.3v-.1l-.2-.1 .1-.1 .2 .3-.2 .3-.3 .2-.3-.1-.3-.2-.1-.2 .3-.5 .4-.2 .5 .2 .3 .5a.75 .75 0 0 1-.8 .7l-.6-.1-.3-.3-.1-.4zM132.4 104.3l.1 .1v.4zM131.9 101.6l.6-.3 .2 .2-.2 .1-.2-.2-.4 .8 .1 .1-.2 .2v-.3l.3-.6-.3 .2zM132.7 101.1l.4 .4 .4 .6zM132.7 101.9l.2-.1 .2 .1 .4 .4 .1-.3 .1 .8 .5 .8 .3-.3v-.2h.1l-.3 .7-.2-.2a2.27 2.27 0 0 0-1.8 .2v-.1a2.13 2.13 0 0 1 1.8-.2l-.5-.6-.1-.4-.2 .1h.1l.2 .6-.1-.1-.3-.5-.1 .1 .2 .3-.2-.1-.2-.4v.2l.4 .5-.3-.2-.3-.4-.1-.4h.1v.1l.1-.2h.2l.1 .1 .2 .1-.2-.3-.1 .1h-.2l.1-.2-.2 .3h-.1zM132.8 108.7l.2-.1-.1 .2zM132.5 107.1h.3l.4-.2 .3 .1-.5 .4-.2-.2h.2l.2-.2-.2 .2h-.3a1.38 1.38 0 0 0-.7 1v.9l.6 .2-.3-.6v-.2h.2v.2l.1-.1-.1-.2v.1h-.2l.2-.4 .1-.2 .3 .1-.1-.2-.2 .1 .3-.4h.1l-.1 .2h.1v.3l.1-.3v-.2h.1l.2-.2 .3-.1-.1 .2v-.1l-.1 .1 .1 .1h.2l-.1 .3-.1 .1-.4-.1 .3 .2 .1 .3-.3 .1-.2-.2v.3l-.2-.2h-.2l.1-.2-.1-.1-.1 .3 .1 .3-.2 .3 .2 .2h.1l.1 .3 .2 .3-.1-.2 .2 .1v-.1l-.3-.1v-.2l.2 .2 .1-.1-.3-.1v-.2l-.2-.1 .3 .1 .2-.4-.1 .4 .1 .2 .2-.1h-.2l.1-.2h.2l-.1-.1-.1 .1v-.1h.2l.1-.1 .2-.1-.3 .5v.2l.1 .1-.3 .1 .1 .3-.1 .2h-.2l.1 .5 .2 .5 .3-.8 .5-.5-.2-.2h-.1v-.1l-.1-.5 .5 .8 .7-.3 .2 .1-.5 .2a1.77 1.77 0 0 0-1.2 2l-.1 .9-.2 .5 .2-1.1a1.12 1.12 0 0 0-.3-1.1l-1-1.2-.6-.5v-.8l.1 .8 .3 .2v-.2h.1l.6 1 .5 .5-.4-.5 .3 .2v-.6l.1 .1 .2-.2-.3 .1-.3-.3-.8-.3-.1-.1v-.5l.1 .1 .1-.1-.1-.1-.1 .1 .1-.4z"/>
<path d="M133.4 114.8h.2v.2l-.3 .8-.1-.2zM133.5 103.6h.1a.25 .25 0 0 1 .3 .1 .25 .25 0 0 1 0 .3l-.1 .4-.2 .1 .2-.7-.2-.1v.4zM133.7 109.1l.1 .5h-.3l.2-.2zM133.8 110.5h.1v.2l-.3 .7zM133.9 108.9v.2zM134 100.4l-.1 .6-.1 .7 .7 .9 .1 .4-.5-.7a.6 .6 0 0 1-.4-.6l.1-.9zM134 101.6l.1 .3zM134 102.8l.3 .4zM134 103.9l.1-.1-.2 .2zM132.8 106.3l1.3-.4 .8 .1 .4 .2 .3 .3v.2l-.1 .3v-.4l-.1-.2a1.7 1.7 0 0 0-1.6-.3l-1 .3zM134 104.8l.4-.1zM134.3 111.7h.1l-.7 1.1h.2l-.1 .2 .3-.1 .8-.9-.8 1.1h-.1l-.4 .1v-.3l-.1 .2v-.1l.3-.7z"/>
<path d="M134.4 101.5l.4 .2-.2 .5-.4-.4 .1-.1 .2 .2zM134.3 114l.1-.1-.2 .2zM134.3 110.1h.2l-.2 .1zM134.4 111.9l.1-.1-.2 .1zM134.2 108.4l.3-.1 .2 .2-.1 .3v.1l-.4 .4-.1-.3h.2l.1-.1-.1 .1h-.2l-.1-.3 .1 .1 .1-.1h-.2h.3l.1-.2v.3l.1-.2v-.2l-.3 .2h-.2zM134.1 104.1l.4-.2-.5 .2zM133.6 106.7l.6-.2-.3 .4 .5-.5 .2-.1-.2 .5 .4-.3-.3 .6 .4-.7 .2 .1-.5 .8h-.7l.2 .2-.2 .3 .1-.1h.2l.1 .3v-.3h-.3l.3-.1 .2 .1-.1 .4-.4 .3-.2-.1 .3-.1 .1-.4-.2 .4-.2 .1-.1-.3 .3 .1-.1-.2-.2 .1 .2-.5-.1-.1 .1-.3h-.1l.6 .1-.1-.1h-.5l-.1-.1-.1 .1 .3-.5-.3 .3zM134.5 112h.2l-.2 .1zM133.5 113.5l.5-.2 .7-.4-.2 .2-.3 .2zM134.6 103.8l.1-.1zM134.4 110.5l.3-.2-.3 .5 .5-.3-.4 .4h.3l-.6 .4-.4 .5-.1 .3 .6-.7 .3-.2h.2l-.8 .6-.6 1.1 .4-1.5h.2l.3-.5-.1 .1-.2 .4-.1-.1zM134.7 100l-.3 1 .1 .3 .8-.1 .5-.3-.2 .3 .3 .5 .5-.7h.1l-.8 1.3 .2-.6-.4-.4-.6 .1a.39 .39 0 0 1-.5-.1v-.6z"/>
<path d="M134.7 115.3l.5 .2-.1 .8-.1 .2-.1-.1 .1-.9-.3 .9-.1 .1-.1-.2zM134.8 108.8l-.1 .2zM134.5 109.9l.3-.1 .1 .1-.4 .1zM134.8 101.2h.2zM134.9 107.6l.1 .4 .1 .1-.2 .4zM134.7 104.4l.3-.3v.2l-.4 .2zM135 110.2h.1zM135.1 109.8h.3h-.3zM135 110.8l.1-.1zM135.1 105.9l.6 .1-.2 .1 .6 1-.5-.9zM135.2 101.8h.3l.1 .1-.1 .3-.3 .2v-.2h.2l.1-.3-.2-.1-.1 .4zM134.8 100.6l.8-.4-.1 .3a1.22 1.22 0 0 1-.8 .6l-.2 .1z"/>
<path d="M135 102.9l.7-.5-.1 .2 .3 .5h-.1v-.1l-.3-.3-.1 .1 .3 .2v.2l.2 .1 .4-.1-.2 .4 .3-.5-.4 .2v-.2l.8-.2-.6 .8v.1l-.3-.1-.2 .1-.1-.1-.1 .1 .1 .1-.5-.2h-.4l.2-.2 .5 .1-.1-.1h-.3v-.1h-.1l-.2-.1h.4l.1 .1h.1l.2 .1 .2-.1-.1 .1 .3 .1 .1-.2-.3-.1-.4 .1h-.1l-.1-.2-.4 .1 .1-.2 .4 .1 .3-.2 .1 .1-.2-.2-.2 .2h-.4h.3l.2-.3-.3 .3h-.2zM135.8 118.2l1 .7h-.3zM135.8 102.6l.3 .1zM136 104.1l.1 .1 .2 .5 .4 .3-.4-.1-.2-.1-.7 .6 .6-.8zM136.1 105.1h.1l-.2 .1zM136.2 106.5l.1 .2zM135.3 105.6l.5 .2 .6-.5-.4 .5 .7 .3-.8-.2 1 .5-.8-.3zM136.4 103.8l.1 .1-.1 .1zM136.5 105.2l.1-.1-.1 .2zM136.6 103.8h.3l.2 .1-.4 .3-.4 .2 .6-.5h-.2l-.2 .2zM137 115.9h.1l.1 .1-.2 .4 .1 .3-.2 .3-.1-.2zM137.5 112.5l.2 .1-.2 .1z"/>
<path d="M137.7 101.2l.3 .2 1-.1-.1 .3v.5l-.1-.6h-.4v.7l.2-.1a.26 .26 0 0 1 .3 .2 .26 .26 0 0 1-.1 .3v-.3h-.4v.5l.2-.4v.3h.3v.2v.8l-.4-.1-.1 .3 .4 .1 .1-.3v.4h-.8v.3v.1l.1-.3 .1 .3 .1-.3 .1 .4 .3-.1 .1-.3v.5h-.8v.2v.1l.1-.2 .1 .3v-.1l.2 .1v-.3l.2 .3 .1-.1v-.1h.1v.4l-.3-.1-.1 .2v-.2h-.2l-.1 .2 .1 .2 .5-.1 .1-.2v.4h-.6l-.1 .2 .7 .1 .1 .1-.6 .1-.1-.1-.1 .1 .1 .1h.6l.1 .1h-1v.4v.1h1v.1l-.6 .1v.1h.6h-.6v.3h.6l-.7 .1 .1 .1-.4 .1 1 .1-.7 .1h-.1l.2 .1-.3 .1-.1 .1 .8 .1 .6 .3 .3 .1 .5-.1 .4-.4-.1 .4-.3 .2-.1 .4-.1-.2-.1 .5-.6-.6-.1 .2h.2a1.58 1.58 0 0 1-.4 1.7l.4 .4 .3 .1h.4l.3-.2 .1-.4-.5-.9 .1-.2 .1 .5 .9 1.2 .1 .8-.1 .7v-.7h-.1v.4l-.6-.5v.2h.2l.2 .2 .1 .3-.2 .3h-.2l.2 .2-.1 .2-.2-.3h-.3l-.1 .3 .2 .3-.3-.2-.1 .5-.1-.6-.2 .6h-.1l.1-.3h-.2l.1 .1v.1h-.3l-.1-.1h.2l-.1-.1v-.4l-.2 .7 .1-.9-.4 .9-.1-.2-.1 .3-.1-1.1-.3 1.1v-.2l-.1 .2h-.1l-.2-1-.1 1v-.1l-.1 .1-.2-.3h.2v.1v-.3v.2h-.2l-.1-.5v.7l-.1-.2-.1 .2-.4-.5-.2-.5h3.7v.1v-.2v.1h-3.7l-.1-.5h1.1l.1 .2h.3l1.6 .1 .8-.1v.1l.1 .1-.1-.3h.2l.3 .4 .1-.2v-.3l-.2-.2-.2 .3h-.2l.2-.4-.2 .2v.3h-.5v-.5h-2.2l-.1 .3h-1.1v-.1l.1 1.1-.2-.3 .3 .6a1.36 1.36 0 0 1-.7-1.6l.1-.4h1.4l.1 .3 .6-.1 .1 .1h.1v-.1h.1v.1h.1l-.1-.5v.4h-.1v-.3l-.1-.1-.1 .4-.1-.4-.5-.1-.1 .3h-1.4l.2-.4h2v-.1l-.1 .1h-1.9l.3-.5h1.6l.1 .3-.1-.4v.1h-1.6l.3-.6 .1-.7h.7v.4l.2 .3 .3 .4 .3 .2 .1 .6v-.6l.1-.1 .1 1.3h1v-.3h.9h.1l.1 .1 .2 .2 .3-.2-.1-.3-.1-.1h-.3l-.1 .3h-.1v-.1v.1h-.9l-.1-.3-.4 .1-.1 .4-.1-.4-.2 .1-.1-.1v-.3h.2v.2v-.2v-.2v.2h-.2v-.4l.1-.1h.2l.4-.5 .2-.5-.3 .5-.5 .4v-.2h.2l.2-.3-.5 .3-.1 .2-.1-.3-.1 .3-.3-.3 .3 .1v-.1h-.4l.2-.1-.2 .1-.1-.2 .1 .1 .1-.1h-.2l-.1-.1 .2 .1v-.2l-.2 .1 .1-.2-.1 .1-.1-.1v-.2h.1l.1 .1v-.2h.1l.2 .6 .3 .1h.2l.6-.2 .1-.5 .2 .1-.2-.1-.4-.5-.2-.2-.1 .2-.1-.2-.4 .2-.2 .5h-.1v-.3l-.1 .4h-.1l.1-.7 .2 .1-.1 .2 .2-.2-.1-.2 .2 .1-.1-.2 .2 .1 .2-.1 .5 .1 .5 .7-.2-.6v-.1h1l.1-.1-1.1 .1-.5-.3h-.5l-.5 .4-.2 .6h-.7l-.1-1.4 .4-.5v.9l.1-1 .1 .1v.6v-.2h.7v.4h.9l.3 .2-.2-.3-.2 .1v-.2l-.1 .2h-.6l.5-.1-.1-.1-.4 .1-.1-.4v.1h-.7v-.2h.9v-.1l-.1 .1h-.8l.1-.3 .4-.2 .2 .5v-.4h.2h-.2v-.2l.1 .1 .3-.1-.1-.1h-.2v.1a.24 .24 0 0 0-.4-.1l-.7 .3a1.33 1.33 0 0 0-.4 1.7l.1 .2a.95 .95 0 0 1-.3 1.2l-.6 1.1-.1 .7 .1 .5a2.43 2.43 0 0 0 .8 1.1l-.4-.2-.4-.6-.2-.5v-.5a3.4 3.4 0 0 1 .8-1.9l.2-.4v-.3a2.06 2.06 0 0 1 0-2l.8-.4 .6-.2 .2 .1 .2-.1-.1-.1-.3 .1v-.9l.2 .1v-.1v-.1l-.1 .1h-.1v-.3h.1l.1 .1v-.2v-.1l-.1 .2h-.1v-.6h.1l.1 .3v-.2v-.2l-.2 .1 .1-1.4 .3 .1v-.3v-.1h-.1v.3h-.2v-.8h.2l.1 .4 .1-.5 .1 .5 .3-.1 .1-.3-.3-.2-.2 .1-.1-.1-.1 .2h-.2v-.6h.2l.1 .3v-.3v-.2l-.1 .2h-.2v-.8h.1l.1 .5 .1-.6-.1-.1-.1 .2h-.1zM138.1 106.6h.5a.21 .21 0 0 1 .4 .1l-.9 .1zM138.2 118.2l.2-.2-.4 .6v.8v.3l.2 .4a.14 .14 0 0 0 .2 .2 .14 .14 0 0 0 .1-.1 2.09 2.09 0 0 0 .1-2.1h.1a1.96 1.96 0 0 1-.3 2.4l-.2-.2a1.71 1.71 0 0 1 0-2.1zM138.4 104.8v.2zM138.5 109.5v.3zM138.5 101.6l.1 .1v.4zM138.6 111.9l.1 .1v.1l-.1-.1zM138.7 103.8v.1zM138.5 107.7h.5zM138.5 108.1l.4-.1 .1 .1-.3 .1-.2-.1zM138.9 112.5h.1l.1 .1h-.2zM139.2 100.3l.1 .1-.1 .1z"/>
<path d="M139.3 111.9v.2l-.1-.1zM140 103.8h.4l.5 .9 .1-.4 .1 .4 .2 .2h-.1l-.2-.2v.1l.6 .7-.8-.7-.7 .2 .6-.2v-.2l-.1-.2-.5-.3-.1-.2 .5 .4-.3-.4h.1h-.3zM140.3 100.9l.6 .9zM140.4 101.5l.2 .3zM140.4 105.3l.5 .5 .7-.1-1.2 .7 .7-.5-.3-.1-.7 .3 .7-.3zM140.5 113.6l-.1 .1zM140.5 109.4v.2a.51 .51 0 0 0 .1 .7 3.1 3.1 0 0 1 1 1.7v.1l-.3-.8-.9-1.3-.1-.2zM139.1 108.3l.4 .2h.5l.2-.1 .4-.5 .2 .3v.8v-.7l-.2-.2-.3 .4-.4 .2-.5-.1zM140.2 106.2l.7-.3zM140.9 101.8l.4 .6zM141 103.7h.1l-.1 .1zM141.2 106.6v.3z"/>
<path d="M141.3 111.7l.1 .3zM140.2 102.8l.6 .3 .1 .4 .2-.2 .4 .3 .1-.1h-.2v-.1h.2h-.2v-.2h.3v.2l.3-.1h-.2l-.1-.2-.3 .1-.1-.2 .1 .2-.2 .1v-.3h.1l.3 .1-.2-.2h.2l.2 .1v-.1l-.5-.1-.3 .4-.2-.3 .2 .1 .2-.2h.2l.1-.1-.3 .1v-.2h-.5l.6-.1 .4 .2 .6 .6h-.2l-.2 .4 .1 .1 1 .6 1.7 2-.1-.2a2.3 2.3 0 0 1-.2-1.7v.2a2.07 2.07 0 0 0 .3 1.4l.1 .1 .2-.6 .6-.4-.5-.7h.4l.2 .2-.1-.3-.5 .1-.3-.4h-.2l-.3 .1-.1 .5v-.3l.1-.2 .2-.2 .3-.1v-.8l.1 .9 .3 .4 .2-.1v.1l.1-.2-.1 .1h-.2l.2-.3h.3l.1 .2 .2-.1h.6l.1-.2-.2 .2h-.5l.1-.2 .1 .1 .4-.5 .2 .1 .2-.1v-.1l-.3 .1h-.1l-.1-.1-.3 .5h-.1l-.1-.1-.2 .2v-.1l.1-.2h.2l.3-.3-.3 .3h-.2l.3-.4 .2-.1 .3 .2 .2-.2 .2 .1 .1 .6 .1-.2 .1 .1-.1 .5-.2-.1-.1-.5v.3l-.1 .2h-.1v-.4l-.2 .5-.1-.2-.2 .3-.2-.3-.2 .1v.3l-.1-.2 .3 .4-.3 .1v.2l-.4-.5 .4 .7-.6 .4-.3 .5a.61 .61 0 0 0 .1 .8l.7 1.4-.5 1-1.3 1.4 1.8-1.6-.2 .2a6.3 6.3 0 0 0-1.8 2l-.2 1.2-.1-1.2-.2-.6 .2 .1v-.1l-.1-.2-.1 .1-.1-.1v-.2l.1 .1-.1-.2a1.99 1.99 0 0 0-1.3-.6l-.2-.2 .9 .2 .4 .3a1.51 1.51 0 0 1 .6 1.3l.2-.3 .1-.4-.1-.6-.2-.4h.2l.1 .2 .3-.5-.2-.1v.3l-.4 .1-.2-.2-.1-.3 .2 .1v.2v-.3h-.2v-.2l.1-.2 .1 .1v.1l.1 .1 .2-.1h-.2l.2-.2 .1 .2v.2l-.3 .1 .2 .1-.2 .1v.1l.3-.1v-.1l.1-.3 .4 .3 .1-.9-.2-.1 .1 .2-.2 .2v-.5l-.1 .1-.2-.3 .1 .2-.2 .2 .2-.1 .1 .1-.3 .1-.2-.1-.2-.5-.1 .1-.1 .7v-.2h-.1l.1-.2-.2 .1-.4-.2v-.6h.3l-.2 .3 .2 .2-.1-.2 .2-.2 .1 .3-.1 .1-.1-.2v.1l.2 .2h.1v-.3l.2-.1 .1 .1v.2h.2l.1 .1-.1-.2-.2 .1 .5-.3 .2 .4v-.2l-.4-.8 .2 .1-.2-.1-.1-.3 .5 .4-.2 .2 .6 1-.1 .7 .2 .1-.4 .1-.3 .3v.9l1-1.1 .1-.7-.1-1 .2 .8-.1 .9 .3-.4 .2-.4a4.4 4.4 0 0 0-2.2-3.2l-.1-.2 .4 .2-.6-.7-1-.8h-.1v.2l-.1-.2-.3 .2-.2 .3v-.4l.5-.2-.1-.1-.6 .2 .1-.3-.1-.1h-.2l-.1 .3-.1-.3v.5l-.3-.8zM141.3 100.2l.8 .4 .2 .2v.2h-.4l-.4-.2-.2-.3zM141.2 106.2l.2-.1-.6 .9zM141.5 101.7h.1l.2 .2-.2-.1h-.1v.5l-.1-.2zM141.4 106l.2-.1-.2 .2zM141.3 104.5h.2l.2-.2 .1 .2 .3-.1-.3 .2 .2 .2 .1 .3h.2l.7-.1-.2 .2 .3-.1 .1 .1-.6 .4h-.6l-.2-.1 .4 .1 .1-.1h-.5l-.1-.2 .3 .2v-.2l.4 .2-.1-.2h.4l-.1 .2 .3-.2-.3-.1h-.5l-.1-.1-.1 .2-.2-.2h.2l-.1-.1 .1-.2-.5-.2-.2 .1zM141.6 104.1l.1-.1v.1l-.2 .1zM141.7 109.7l.7 .2 .2 .2zM141.8 110.1h.1zM141.8 104.2h.1l.1 .1zM142 104.6l.2 .1v-.1l.2 .2-.3 .2 .1-.2z"/>
<path d="M142 108v-.1l.1 .5-.2-.3zM142 110.7l.2 .1zM142.1 107.6v.2zM142.1 110.3l.4 .3 .3 .4zM141 100.9l.6 .3 .8-.1 .1-.2-.3-.9 .2 .3 .2 .6-.1 .2-.3 .3-.7-.1-.4 .4 .1-.4zM142.2 113.2l.8 .8-.4-.3zM142.1 103.7h.2v.1zM142.2 104.4l.1 .1zM142.2 113.6l.5 .4zM142.3 106.2l.4 .2v.2l.1-.2 .2 .1v.1l-.2 .1 .1 .2v-.1h.3h-.3l.2-.3 .2 .2-.1 .4-.2 .1 .2 .2-.1 .1 .3-.1-.1-.1 .1-.1v-.3l.2 .1-.1 .1v.1l-.1 .1 .1 .2 .1-.2 .1 .1-.1 .3-.1 .1-.2-.2-.2 .1-.2-.4-.4-.1-.2-.2-.2-.3h.1l.3 .4 .3 .1 .3-.1-.3 .1v-.3l-.2 .1-.4-.3h-.1v-.3l.3 .3 .2-.2zM142.3 112.2l.1 .2zM142.4 113l.6 .4-.4-.1z"/>
<path d="M142.4 101.3l.2 .4 .2 .1-.5 .3-.1-.3 .2 .1v-.2l-.1 .1h-.1zM142.5 112.5l.8 .7a.56 .56 0 0 1-.6-.4zM141.5 106.2l.4-.2 .5-.1 1.5 .3-.1 .1-1.2-.3-.5 .1-.5 .2-.2 .5v-.3zM142.4 108.3h.2l.3 .3 .1 .3-.1 .1h-.2l.3 .1-.1 .2 .3 .4-.3-.2-.6-.8 .5 .2 .1-.1-.6-.1v-.2l.5 .1-.3-.1v-.1l-.2 .1zM142.5 112.9l.6 .4zM142.1 110.6l.7 .5 .3 .4-.6-1.1 .3 .3a1.16 1.16 0 0 1 .3 1.3h.2l.1 1.1-.4-.9 .2 .4a.9 .9 0 0 0-.3-.8l-.1-.1h.2l.1 .2-.1-.2h-.2l-.7-.7h.1l.8 .6zM142.6 111.6l.1 .2zM142.6 111.9l.3 .2zM139.4 119.1h.1a1.14 1.14 0 0 0 1.4-.4l1.4-1.2 .4-.2-.9 .8a3.1 3.1 0 0 1-1.7 1.1h-.5zM142.4 104.7l.3-.1 .2 .2-.2 .1zM143 103.6l.1 .1 .1 .4zM143 100.4l.1 .4v1l-.5 .6-.2 .5 .2 .5 .3-.3-.2 .4 .3 .6-.3-.4-.2 .1 .1-.3-.3-.2v-.3l.1-.6 .6-.8z"/>
<path d="M143 102.8h.1l-.2 .2zM143.2 103.6h.2v.2zM143.3 108.3h.1v.2zM143.3 104l-.1 .4v-.1zM143.3 109.6l.3 .3zM143.3 102.1h.1l.2 .4-.1 .2-.2 .3 .1 .1-.2-.1 .1-.2-.1-.4zM143.4 104.7l.1 .2zM142.8 103.5l.1-.1a1.66 1.66 0 0 1 1.7 .4l-.9-.3-.5-.1-.4 .2zM143.4 106.7h.1l-.1 .2zM143.6 105l.1 .1zM143.6 101.5l-.1 .4zM143.8 111.5v1.4l-.1-.8z"/>
<path d="M144 102.9l-.1 .2zM144 112.8l.1 .1zM143.9 101.1h.1l-.3 .3zM143.7 101.9l.3-.1h.2l.2 .5-.3 .6 .1-.6-.1-.4 .1 .5h-.1l-.1-.1-.1 .4-.3 .4 .1-.6h.1l.1 .1v-.2l-.1 .1h-.1l-.1-.5h.3h-.3zM144.1 111.4a1.46 1.46 0 0 0-.1 1.2v.1l-.1-.7zM143.7 117.1l.2-.1a.55 .55 0 0 1 .7 .6 .55 .55 0 0 1-.9 .3l-.1-.1v-.2l.2 .2a.44 .44 0 0 0 .6 0 .44 .44 0 0 0 0-.6 .44 .44 0 0 0-.6 0l-.1 .4h-.1v-.2zM144.2 107.1l.2 .2-.2-.1zM144.4 106.9l.3 .4zM144.4 101.6l.2 .2zM144.3 111.5l.2-.1-.4 .4zM144.3 110.8l.2-.1zM144.5 103.3l.1 .2z"/>
<path d="M143.4 117.3l.1-.1-.2 .5 .2 .3 .4 .2h.4l.3-.2 .2-.2v-.5l-.2-.3a.75 .75 0 0 1 .2 .9 .75 .75 0 0 1-.9 .4l-.3-.2-.3-.3-.1-.2zM144.7 109.1h.1l-.1 .1zM144.7 101.6l.3 .5zM144.6 112.1l.2-.1-.5 .4zM144.8 101.5l.2 .2zM144.7 102.7l.3-.1 .4 .3a.46 .46 0 0 1 .2 .6l-.5-.6-.4-.2zM144.1 111.2l.5-.2 .7 .1h-.8l-.3 .2zM144.5 111.8l.5-.2 .1 .2-.1 .1v-.2zM145 110.7h.1zM144.8 112.1l.2-.1 .4 .1h-.5l-.5 .6zM145 112.6h.1l-.1 .1zM144.9 111.2h.2z"/>
<path d="M145.2 104.8v.1zM145.1 111.6l.3 .1 .2 .1zM144.7 113.1l.6-.1-.4 .1zM145.2 111.8l.4 .3zM145.1 109.9l.2-.1-.5 .5zM145.3 103.2l.1 .2zM145.3 105.7l-.1 .3zM145.2 102l.3-.1 .2 .1-.4 .4-.1-.2h.2l.1-.2-.3 .2zM145.4 115.8l1.2 .1-.7 .1a.42 .42 0 0 1-.5-.2zM145.5 112.1l.2 .3zM145.4 113l.1-.1-.1 .1zM145.5 106.5l.1-.1-.2 .2z"/>
<path d="M145.7 115l1.6 .2 .5 .2-1.9-.2-.2-.1zM145.3 102.6l.4-.1 .7 .3zM145.6 106.7l.1-.1-.2 .2zM145.8 110.3l.1 .2zM144.7 110.5l.2-.1 .1 .1v-.1l.1-.1 .7-.2 .3 .3-.1 .1v-.2l-.2-.1-.4 .1v.2l-.1-.1-.6 .2zM145.9 107.5l.2 .3zM145.9 102.5h.5l.2 .2v.2l-.3-.3zM146 110.7l.3 .2zM146 105.4h.1v.2l.1 .2 .5 .2 .2-.2h-.5l-.2-.1v-.2h.3l-.3 .1 .3 .1 .3-.2v.2l.4-.2 .1 .2-.1 .2h.2v.1a.95 .95 0 0 1-1.5-.5zM146.1 107.4l.2 .2zM145.9 109.6l.4-.1zM146.4 110.8l.2 .4-.2-.2z"/>
<path d="M146.4 107.6l.1 .2v.1zM145.7 115.5l1.4 .1zM146.5 110.8l.2 .2 .1 .3zM146.6 107.6v.1zM146.3 114.3l.3-.1-.1 .1zM145.7 114l.6-.4h.4l-.1 .2-.5 .3h-.2l.6-.4-.9 .4zM146.7 106.7l.2 .1zM146.7 101.8l.2-.1-.1 .3h-.3zM145.9 104.9l.2-.1v.2l.1 .1 .4 .1 .1-.2 .1 .1h.2l-.1-.1-.5-.3v-.1l.5-.2 .2 .2 .1 .3-.2 .3-.4 .1-.5-.1zM146.2 108.3l.6-.3h.2l-.5 .6-.1-.1 .5-.4zM145.5 107.2l.8-.2 .8-.1zM146.8 106.5l.4-.1 .2 .2-.2 .2v-.2z"/>
<path d="M147.2 104.5h.1l-.1 .1zM147.3 103.4l.4 .2 .3 .4-.1 .8-.3 .4-.1-.1-.1-.1 .2-.1h-.1l.1-.6 .1-.2v-.1h.1l-.1-.1-.1 .3-.2 .1 .1-.6-.2-.1zM147.4 105.1l-.2 .3zM147.5 105.4l.7 .5-.5 .2h-.2v-.1h.2l.3-.2-.2-.1v.2h-.3l-.1-.3zM147.3 110.2l.3 .1 .3-.1-.2 .2 .1 .1-.1 .3-.2-.2-.2 .1v-.2l-.2-.1h.3zM148.1 104.5l.2 .2 .1 .2v.4l-.3 .2-.1-.1 .2-.2-.3 .1-.1-.1 .3-.2-.1-.2h.2zM148.3 105.9l.4 .1zM148.9 100.9l.3 .3a10.4 10.4 0 0 1 1.2 3.5l.6 .9-.1-.1a2.74 2.74 0 0 1-.9-1.9 6.7 6.7 0 0 0-1.1-2.6zM148.5 114.1h.3l.5-.6a.73 .73 0 0 1-.8 .7zM150.1 105.3l1.3 .9-.9-.5zM150.2 107.9v.2zM150.4 107.3v.2z"/>
<path d="M150.2 108.7l.3-.2v.1a1.26 1.26 0 0 0-.6 1 11 11 0 0 1-1.9 4.3l-.1 .2h.4l.4-.7 .1-.2h.3l.3 .1 .1 .2 .1 .2-.1 .3a1.51 1.51 0 0 1-1.6 .9h-1.6l-.5-.1-.2-.1v-.1l.6 .2h1l-1.5-.4 .7 .1a3.6 3.6 0 0 0 2 .2l.5-.1 .3-.3 .3-.5-.1-.4-.3-.1-.3 .1-.4 .8h-.9l.2-.2a11.4 11.4 0 0 0 2.2-4.7zM150.5 103.4h.1a.33 .33 0 0 1 .4 .4 6.3 6.3 0 0 0 1.6 3.3 7.3 7.3 0 0 0-1.7 3.4l-.2 .1-.2-.1-.1-.2 .1-.2a4 4 0 0 1 1.2-2.3l-.1 .1a5.7 5.7 0 0 0-1 2.2l-.1 .2 .1 .2h.2l.1-.2a6.8 6.8 0 0 1 1.6-3.3l-.2-.2a5.1 5.1 0 0 1-1.4-3.1l-.2-.2-.1 .1a6.2 6.2 0 0 0 1.2 2.8 5.4 5.4 0 0 1-1.3-2.8zM150.8 108.6l.2-.1v.1a3.6 3.6 0 0 0-1 2.3l-.1 .4a5.4 5.4 0 0 1-1 1.9l.1-.1a8.5 8.5 0 0 0 1.1-3.1l.3-.8zM151.1 106.4a.75 .75 0 0 1 .4 1h-.1l.1-.2a.81 .81 0 0 0-.4-.8zM150.6 108.5l.6-.4zM150.2 108.4l1.1-.6zM151.7 106.6l.4 .4-.2 .2 .1-.2zM151.5 107.7l.5-.2zM164.9 99.8h2.8v6.3h-2.8v-1.4h.3v1a.15 .15 0 0 0 .1 .1 .15 .15 0 0 0 .2-.1v-.8h1.8a.15 .15 0 0 0 .2-.2 .15 .15 0 0 0-.2-.1h-2l-.1 .1h-.3v-2.5h.3l.1 .2h2a.15 .15 0 0 0 .2-.1 .15 .15 0 0 0-.2-.2h-1.4l1.5-.9 .1-.1-.1-.1h-2.1a.15 .15 0 0 0-.1 .1 .15 .15 0 0 0 .1 .2h1.5l-1.6 .9h-.3v-2.1h.3l.1 .2h2a.15 .15 0 0 0 .2-.1 .15 .15 0 0 0-.2-.2h-2l-.1 .1h-.3zM189 114.2h2.3v3h-2.3v-1.6h.3l.1 .7 .4 .5 .4 .2 .6-.2a.27 .27 0 0 0 .2-.4 .27 .27 0 0 0-.5 0 .46 .46 0 0 1-.6-.3 .76 .76 0 0 1 .4-1.1h.2a.28 .28 0 0 0 .5 0 .28 .28 0 0 0-.3-.4l-.5-.1-.4 .1-.3 .3-.2 .7h-.3z"/>
<circle cx="129.4" cy="98.9" r=".05"/>
<circle cx="133.7" cy="98.3" r=".06"/>
<circle cx="135.4" cy="96.9" r=".08"/>
<circle cx="137.6" cy="99" r=".05"/>
<circle cx="137.6" cy="99.4" r=".1"/>
<circle cx="137.7" cy="100" r=".12"/>
<circle cx="139.2" cy="99.9" r=".11"/>
<circle cx="139.3" cy="99.4" r=".11"/>
<circle cx="130.4" cy="107.5" r=".05"/>
<circle cx="130.9" cy="112.9" r=".05"/>
<circle cx="131.1" cy="100.7" r=".07"/>
<circle cx="131.9" cy="110.7" r=".06"/>
<circle cx="132.9" cy="108.4" r=".06"/>
<circle cx="132.9" cy="101.6" r=".08"/>
<circle cx="134" cy="109.6" r=".05"/>
<circle cx="134.6" cy="113.8" r=".05"/>
<circle cx="134.7" cy="113.7" r=".06"/>
<circle cx="134.7" cy="108.2" r=".06"/>
<circle cx="135.1" cy="104.4" r=".07"/>
<circle cx="137.4" cy="112" r=".05"/>
<circle cx="137.7" cy="101" r=".11"/>
<circle cx="137.7" cy="100.5" r=".12"/>
<circle cx="137.8" cy="112.5" r=".1"/>
<circle cx="138.1" cy="112.6" r=".08"/>
<circle cx="138.4" cy="112.5" r=".09"/>
<circle cx="138.5" cy="105.8" r=".05"/>
<circle cx="138.7" cy="112.5" r=".06"/>
<circle cx="139.2" cy="100.9" r=".09"/>
<circle cx="139.2" cy="112.5" r=".08"/>
<circle cx="140.6" cy="105.2" r=".1"/>
<circle cx="141.1" cy="104.1" r=".06"/>
<circle cx="142.3" cy="109" r=".1"/>
<circle cx="142.3" cy="107.4" r=".05"/>
<circle cx="142.5" cy="104.9" r=".09"/>
<circle cx="142.6" cy="103.2" r=".05"/>
<circle cx="143.2" cy="109.4" r=".07"/>
<circle cx="144" cy="108.8" r=".05"/>
<circle cx="144.1" cy="108.9" r=".05"/>
<circle cx="144.2" cy="112.6" r=".09"/>
<circle cx="144.4" cy="112.8" r=".06"/>
<circle cx="144.4" cy="111.9" r=".06"/>
<circle cx="144.7" cy="111.4" r=".08"/>
<circle cx="144.8" cy="110.7" r=".09"/>
<circle cx="145.4" cy="112.8" r=".04"/>
<circle cx="145.4" cy="106.7" r=".06"/>
<circle cx="145.4" cy="105.6" r=".05"/>
<circle cx="145.6" cy="110.4" r=".08"/>
<circle cx="145.8" cy="107.4" r=".06"/>
<circle cx="146.3" cy="104.8" r=".08"/>
<circle cx="146.5" cy="105" r=".12"/>
<circle cx="146.5" cy="106.8" r=".06"/>
<circle cx="147" cy="106.6" r=".06"/>
<circle cx="147.9" cy="110.6" r=".09"/>
<circle cx="148" cy="110.3" r=".05"/>
</g>
<g fill="none" stroke="#000" stroke-width=".13">
<path d="M88 18.2v1.3M92 18.2v1.3M118 18.2v1.3M122 18.2v1.3M20.3 32.7h-2.7v3.4h-3v11.6h3v3.4h2.7M23.1 32.7h3.6M29.4 32.7h3.6M32.8 26.8h8v4.5h-8M35.8 32.7h2.6v4.7h2.9M38.8 24.7v.5M40.3 24.7v.5M40.8 24.7v.5"/>
<path d="M41.3 37.5v8.9h-2.9v4.7h-2.6M42.3 24.7v.5M42.9 30.8v3.3h13.3v-3.3M42.9 27.3v-8.1h-.6v-.5h14.6v.5h-.7v8.1M49.2 40v.5M50.7 40v.5M52.2 34.4h1.8M53.6 36v.5M55.1 36v.5M55.6 36v.5M57 32.5v.5M57 36v.5"/>
<path d="M58.4 32.5v.5M59.9 29.9h.6l-.3 .3zM65.7 28.1h-4v11.8h4M67.3 34h.9M67.7 33.5v1M69.8 28.1h4v2.4M73.8 37.5v2.4h-4M73.8 32.7v2.6M77.1 31.9v.6M78.5 31.9v.6M80.1 20.1v16M84 21.2v11h.5"/>
<path d="M85.5 20h1.5v-1.8h6v1.8h1.5M86.8 37.2h7.4M96 21.2v11h-.4M98.7 39.6v.5M100.2 39.6v.5M101.9 37.8h.6M101.9 39.3h.6M101.9 39.8h.6M108.5 38.7h.5M114 21.2v11h.5M115.5 20h1.5v-1.8h6v1.8h1.5M126 21.2v11h-.4"/>
<path d="M130.1 20.1v16M134.9 29.9h.6l-.3 .3zM140.7 28.1h-4.1v11.8h4.1M142.2 34h1M142.8 33.5v1M144.7 28.1h4.2v2.4M148.9 37.5v2.4h-4.2M148.9 32.7v2.6M150.5 23.5v.5M151.9 23.5v.5M152 31.7h2.4v2.4h-2.4zM153 24.7h2.4v2.4h-2.4z"/>
<path d="M153.7 29.4v.5M153.8 21.6h1.1v.2h-1.1zM154.2 21.2h.3v1h-.3zM155.2 29.4v.5M155.3 21.6h1.2v.2h-1.2zM157.2 26.9h5.3v2.5h-5.3zM157.5 36.9h.6M157.5 38.4h.6M157.5 35h.6M157.5 36.4h.6M157.6 33h.5M157.6 34.5h.5"/>
<path d="M157.8 21.6h1.8v.2h-1.8zM160.1 21.6h1.1v.2h-1.1zM160.9 36.9h.6M160.9 38.4h.6M160.9 36.4h.6M160.9 35h.6M161 33h.5M161 34.5h.5M162.1 39v1.7M163.4 23.8v.5M164.6 30h.5M164.6 31.5h.5"/>
<path d="M164.7 26h2.8M164.7 29.4h2.8M164.9 23.8v.5M171.9 25.2v-8.5h9.2v14.7h-2.1M171.9 29.6v1.8h2.1M173.3 20.6v10.2M174.2 32.7h-2.6v4.7h-2.9v8.9M177 32.7h3.6M178.2 20.6v10.2M179.7 20.6v10.2M180.4 27.9v-7.3h-10.1v10.2h10.1v-2.3M181.4 30.1v1.6h-1.7"/>
<path d="M183.3 32.7h3.6M189.7 32.7h2.7v3.4h3v11.6h-3v3.4h-2.7M22.3 52.3h-1.6v.3h-2.8M23.1 51.1h3.6M23.5 55.2l.5-.4v.8zM24.5 55.5h1M24.5 58.4h.8M27.5 58.9h.5M29.4 51.1h3.6M42 47.2v.5M42.6 58.5h.5M42.6 60h.5"/>
<path d="M43.4 47.2v.5M44.8 59.9v.5M46.2 59.9v.5M46.3 42.7v.5M46.3 47.5v.5M47.7 42.7v.5M47.7 47.5v.5M47.7 52.4v.5M49.1 48.3v.8h.7M49.2 52.4v.5M49.6 52.4v.5M49.8 42.9h-.7v.7"/>
<path d="M51.1 52.4v.5M51.3 59.6h.5M51.5 52.4v.5M53 52.4v.5M54.3 51.2v.5M54.5 55.7v-.2h3.2v.2M54.5 58.5v.2h3.2v-.2M54.6 42.9h.7v.7M55.3 48.3v.8h-.7M55.8 51.2v.5M58 43.3h.5M58 44.7h.5"/>
<path d="M60.2 44.4v.4M60.5 47.2h.4M60.5 48.7h.4M61.7 44.4v.4M63.2 46.1v.5M63.2 49.5v.5M64.7 46.1v.5M64.7 49.5v.5M65.2 50.9v-5.9h3.7v5.9M69.4 52.2h.5M69.4 53.7h.5M71.6 51v1.8"/>
<path d="M72.3 47.9v.4M73.7 47.9v.4M74.6 51v1.8M79.3 41v.4M80.3 41v.4M80.8 40.8v.4M80.9 42.9h.3M80.9 43.9h.3M82.3 40.8v.4M82.7 43.6v-3.9h2v3.9M86.8 41.3h7.4M89.8 41.7h.4"/>
<path d="M89.8 43.1h.4M89.8 44.2h.4M89.8 42.7h.4M90.4 52h-.3v3.3h.3M92.6 52h.3v3.3h-.3M93 43.6h.4M93 41.7h.4M93 43.1h.4M93 45h.4M94.6 53.1h.5M94.6 54.6h.5M94.6 50.6h.6"/>
<path d="M94.6 49.2h.6M94.7 55.1h.5M94.7 56.6h.5M94.7 51.1h.5M94.7 52.6h.5M97 49.7h-.2v5.5h.2v1.7M99.2 43.7h.4M99.2 45.2h.4M99.2 45.6h.4M99.2 47.1h.4M100.5 43.3h.5M100.5 41.8h.5"/>
<path d="M101.9 41.2h.6M102 49.7h.2v5.5h-.2M102.6 52.4v.6M103.8 48.6v.6M104.1 52.4v.6M104.4 42h-.6v.6M107.9 52.5v.6M108.5 40.2h.5M109.4 52.5v.6M110.4 42h.6v.6M111 48.6v.6h-.6M111.7 54.1h.4"/>
<path d="M111.7 55.5h.4M112.3 56.5h2.4v2.4h-2.4zM112.5 47.4v.6M112.9 50.7h.6M112.9 52.1h.6M113.8 52.6v3.1h1.8M113.9 47.4v.6M115.5 43.5h.5M115.5 45h.5M115.7 56.7h2.7v1.9h-2.7M116.5 50.7h.4M116.5 52.1h.4"/>
<path d="M116.7 48.4v.6M118.1 52.5v3.1M118.1 48.4v.6M121 56.2v1.3h3.7M121.5 48.7h.6M121.5 50.2h.6M122.9 43.2h-.3v3.3h.3M124.7 50.6h-3.7v1.3M125 48.7h.5M125 50.2h.5M125.1 43.2h.3v3.3h-.3M127.9 44.5v1.3h1.4"/>
<path d="M130.6 43.1h5.2v2.7h-5.2zM133.8 47.7h-.9v10.2h.9M136.4 43.6v.4M137.3 47.7h.9v2.3M137.9 43.6v.4M139 42.4h1.5M139 44.6h1.5M139.5 45.4h.5M139.5 46.9h.5M140.5 43.3v.4M140.5 55.6h-2.3v2.3h-.9M142.2 44.2v.6"/>
<path d="M142.7 46.9h-.8v12.2h.8M143.6 44.2v.6M145.1 43h1.8M145.1 44.1v.8M145.1 46h1.8M146.2 46.9h.9v2.3M149.5 56.7h-2.4v2.4h-.9M149.5 42.2h.5M149.5 43.7h.5M149.6 44.5h.5M149.6 46h.5M151.1 55.2h8.1v4.5h-8.1"/>
<path d="M153.2 46.9v.5M154.6 46.9v.5M155.1 43.5v.5M155.1 40.1v.5M155.1 46.9v.5M155.9 53v.5M156.6 43.5v.5M156.6 40.1v.5M156.6 46.9v.5M157 40.5v.2M157 44.1v.3M157.4 53v.5"/>
<path d="M157.9 53v.5M157.9 49.6v.4M159.4 53v.5M159.4 46.4h.5M159.4 47.8h.5M159.4 49.6v.4M159.9 53v.5M159.9 49.6v.5M161.4 53v.5M161.4 49.6v.5M162.1 44.1v.3M162.2 47h-.4v6.2h.4"/>
<path d="M162.5 40.5v.5M162.5 43.9v.5M163.6 55.7h2.4v2.4h-2.4zM163.9 40.5v.5M163.9 43.9v.5M167.6 47h.4v6.2h-.4M168.4 53.5v.5M168.7 46.4h2.9v4.7h2.6M169.9 53.5v.5M177 51.1h3.6M183.3 51.1h3.6M17.9 60.3h2.8v.3h1.6"/>
<path d="M20.3 73.7h-2.7v3.4h-3v11.6h3v3.4h2.7M23.1 73.7h3.6M23.8 63v-2.1h12.3v2.1M23.8 71v2.2h12.3v-2.2M23.8 66v2M27.5 60.4h.5M29.4 73.7h3.6M35.8 73.7h2.6v4.7h2.9M36.1 66v2M41.3 78.5v8.9h-2.9v4.7h-2.6M51.3 61h.5M53.5 61a3.5 3.5 0 0 1 2.5-1h33a3.5 3.5 0 0 1 3.5 3.5v48a3.5 3.5 0 0 1-3.5 3.5h-33a3.5 3.5 0 0 1-3.5-3.5v-48a3.5 3.5 0 0 1 1-2.5z"/>
<path d="M53.6 74.6v-1h3.8v1M87.6 74.6v-1h3.7v1M93.5 74.3l.4-.2h.7a.7 .7 0 0 1 .7 .7v1.4a.7 .7 0 0 1-.7 .7h-.6a.7 .7 0 0 1-.7-.7v-1.5zM96 74.3l.4-.2h.7a.7 .7 0 0 1 .7 .7v1.4a.7 .7 0 0 1-.7 .7h-.6a.7 .7 0 0 1-.7-.7v-1.5zM98.9 63v-2.1h12.3v2.1M98.9 66v2M98.9 71v2.2h12.3v-2.2M99.9 76.8h1.4M99.9 78.9h1.4M100.8 79.9h5.2v2.8h-5.2zM101.3 77.6v.5M102.5 77.5v.5"/>
<path d="M103.9 77.5v.5M104.1 78.8v-2.7h1.9v2.7M106.1 78.8v-2.7h2v2.7M107.2 79.9h1.4v1.4M108.3 77.5v.4M109.8 77.5v.4M111.2 66v2M173.8 63v-2.1h12.3v2.1M173.8 71v2.2h12.3v-2.2M173.8 66v2M174.2 73.7h-2.6v4.7h-2.9v8.9M177 73.7h3.6"/>
<path d="M183.3 73.7h3.6M186.1 66v2M189.7 73.7h2.7v3.4h3v11.6h-3v3.4h-2.7M20.3 93.9h-2.7v3.4h-3v11.6h3v3.4h2.7M23.1 93.9h3.6M23.1 92.1h3.6M29.4 93.9h3.6M29.4 92.1h3.6M35.8 93.9h2.6v4.7h2.9M41.3 98.7v8.9h-2.9v4.7h-2.6M53.6 95.4v1h3.8v-1M87.6 96.4h3.7"/>
<path d="M168.7 87.4h2.9v4.7h2.6M174.2 93.9h-2.6v4.7h-2.9v8.9M177 92.1h3.6M177 93.9h3.6M183.3 92.1h3.6M183.3 93.9h3.6M189.7 93.9h2.7v3.4h3v11.6h-3v3.4h-2.7M23.1 112.3h3.6M23.8 115v-2.1h12.3v2.1M23.8 118v2M29.4 112.3h3.6M36.1 118v2"/>
<path d="M48.4 101.9l.4-.2h1.5a.7 .7 0 0 1 .6 .7l.1 .6a.7 .7 0 0 1-.8 .7h-1.3a.7 .7 0 0 1-.8-.7l.1-.8zM98.9 115v-2.1h12.3v2.1M98.9 118v2M111.2 118v2M168.1 113.8l.4-.2h.7a.7 .7 0 0 1 .7 .7v1.4a.7 .7 0 0 1-.7 .7h-.6a.7 .7 0 0 1-.7-.7v-1.5zM168.7 107.6h2.9v4.7h2.6M173.8 115v-2.1h12.3v2.1M173.8 118v2M177 112.3h3.6M183.3 112.3h3.6M186.1 118v2M23.8 123v2.2h12.3v-2.2"/>
<path d="M98.9 123v2.2h12.3v-2.2M146 126.3l.4-.2h1.5a.7 .7 0 0 1 .7 .7v.6a.7 .7 0 0 1-.7 .7h-1.4a.7 .7 0 0 1-.7-.7v-.7zM146.3 122.2l.4-.2h1.5a.7 .7 0 0 1 .7 .7v.6a.7 .7 0 0 1-.7 .7h-1.4a.7 .7 0 0 1-.7-.7v-.7zM173.8 123v2.2h12.3v-2.2"/>
<circle cx="67.7" cy="34" r="3"/>
<circle cx="142.7" cy="34" r="3"/>
<circle cx="30.1" cy="67" r="4.6"/>
<circle cx="105.1" cy="67" r="4.6"/>
<circle cx="180.1" cy="67" r="4.6"/>
<circle cx="30.1" cy="119" r="4.6"/>
<circle cx="105.1" cy="119" r="4.6"/>
<circle cx="180.1" cy="119" r="4.6"/>
</g>
<g fill="none" stroke="#000" stroke-width=".15">
<path d="M80.1 36.1h50M80.2 29.6h19.6M80.2 29.6l1 3.9M82.4 24.9h-2.2v4.7M82.4 21.4v4.3M82.4 28.5v1.1M83.7 21.4h-3.7v-1.9h20.1v1.9h-3.8M88.1 31.5h-1.3v2h1.3M88.1 34.2h1.3v1.5M88.1 29.6v6.1h3.8v-6.1M88.6 21.4h2.8M91.9 34.2h-1.3v1.5"/>
<path d="M91.9 31.7h1.3v1.9h-1.3M97.6 24.9h2.2v4.7M97.6 21.4v4.3M97.6 28.5v1.1M99.8 29.6l-1 4M110 20.8v.1M110.2 29.6h19.6M110.2 29.6l1 3.9M112.4 24.9h-2.2v4.7M112.4 21.4v4.3M112.4 28.5v1.1M113.7 21.4h-3.7v-1.9h20.1v1.9h-3.8"/>
<path d="M118.1 31.5h-1.3v2h1.3M118.1 29.6v6.1h3.8v-6.1M118.1 34.2h1.3v1.5M118.6 21.4h2.8M121.9 34.2h-1.3v1.5M121.9 31.7h1.3v1.9h-1.3M127.6 24.9h2.2v4.7M127.6 21.4v4.3M127.6 28.5v1.1M129.8 29.6l-1 4"/>
<circle cx="113.8" cy="55.7" r=".13"/>
</g>
<path d="M85 29v1M87.5 29v1M89.5 24.5h1M92.5 29v1M95 29v1M115 29v1M117.5 29v1M119.5 24.5h1M122.5 29v1M125 29v1" fill="none" stroke="#000" stroke-width=".45"/>
<path d="M171.7 26.3v2.2M175.2 30.4h2.6M175.4 24.6h2.2" fill="none" stroke="#000" stroke-width=".8"/>
<path d="M19.3 53.7h.5M19.3 59.2h.5" fill="none" stroke="#000" stroke-width=".7"/>
<path d="M22.4 54.1h.4M22.4 58.9h.4" fill="none" stroke="#000" stroke-width=".65"/>
<use href="#words"/>
</svg>
